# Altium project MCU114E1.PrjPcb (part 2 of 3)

## Sheet MCU114E1_Power.SchDoc
size 431 x 279 mm; Date: Not shown in title block; ApprovedBy: Not shown in title block; CheckedBy: Not shown in title block; Author: Not shown in title block; CompanyName: Not shown in title block; Engineer: Not shown in title block; Organization: Not shown in title block; Address1: Not shown in title block; Address2: Not shown in title block; Address3: Not shown in title block; Address4: Not shown in title block; DocumentNumber: 5; Revision: Use project parameter SCH_Rev; SheetNumber: 5; SheetTotal: 11; PageSetup: Record=PageOptions¦CenterHorizontal=True¦CenterVertical=True¦PrintScale=1.00¦XCorrection=1.00¦YCorrection=1.00¦PrintKind=0¦BorderSize=5000000¦LeftOffset=0¦BottomOffset=0¦Orientation=2¦PaperLength=1000¦PaperWidth=1000¦Scale=100¦PaperSource=15¦PrintQuality=600¦MediaType=1¦DitherType=10¦PaperKind=Letter¦PrintScaleMode=1

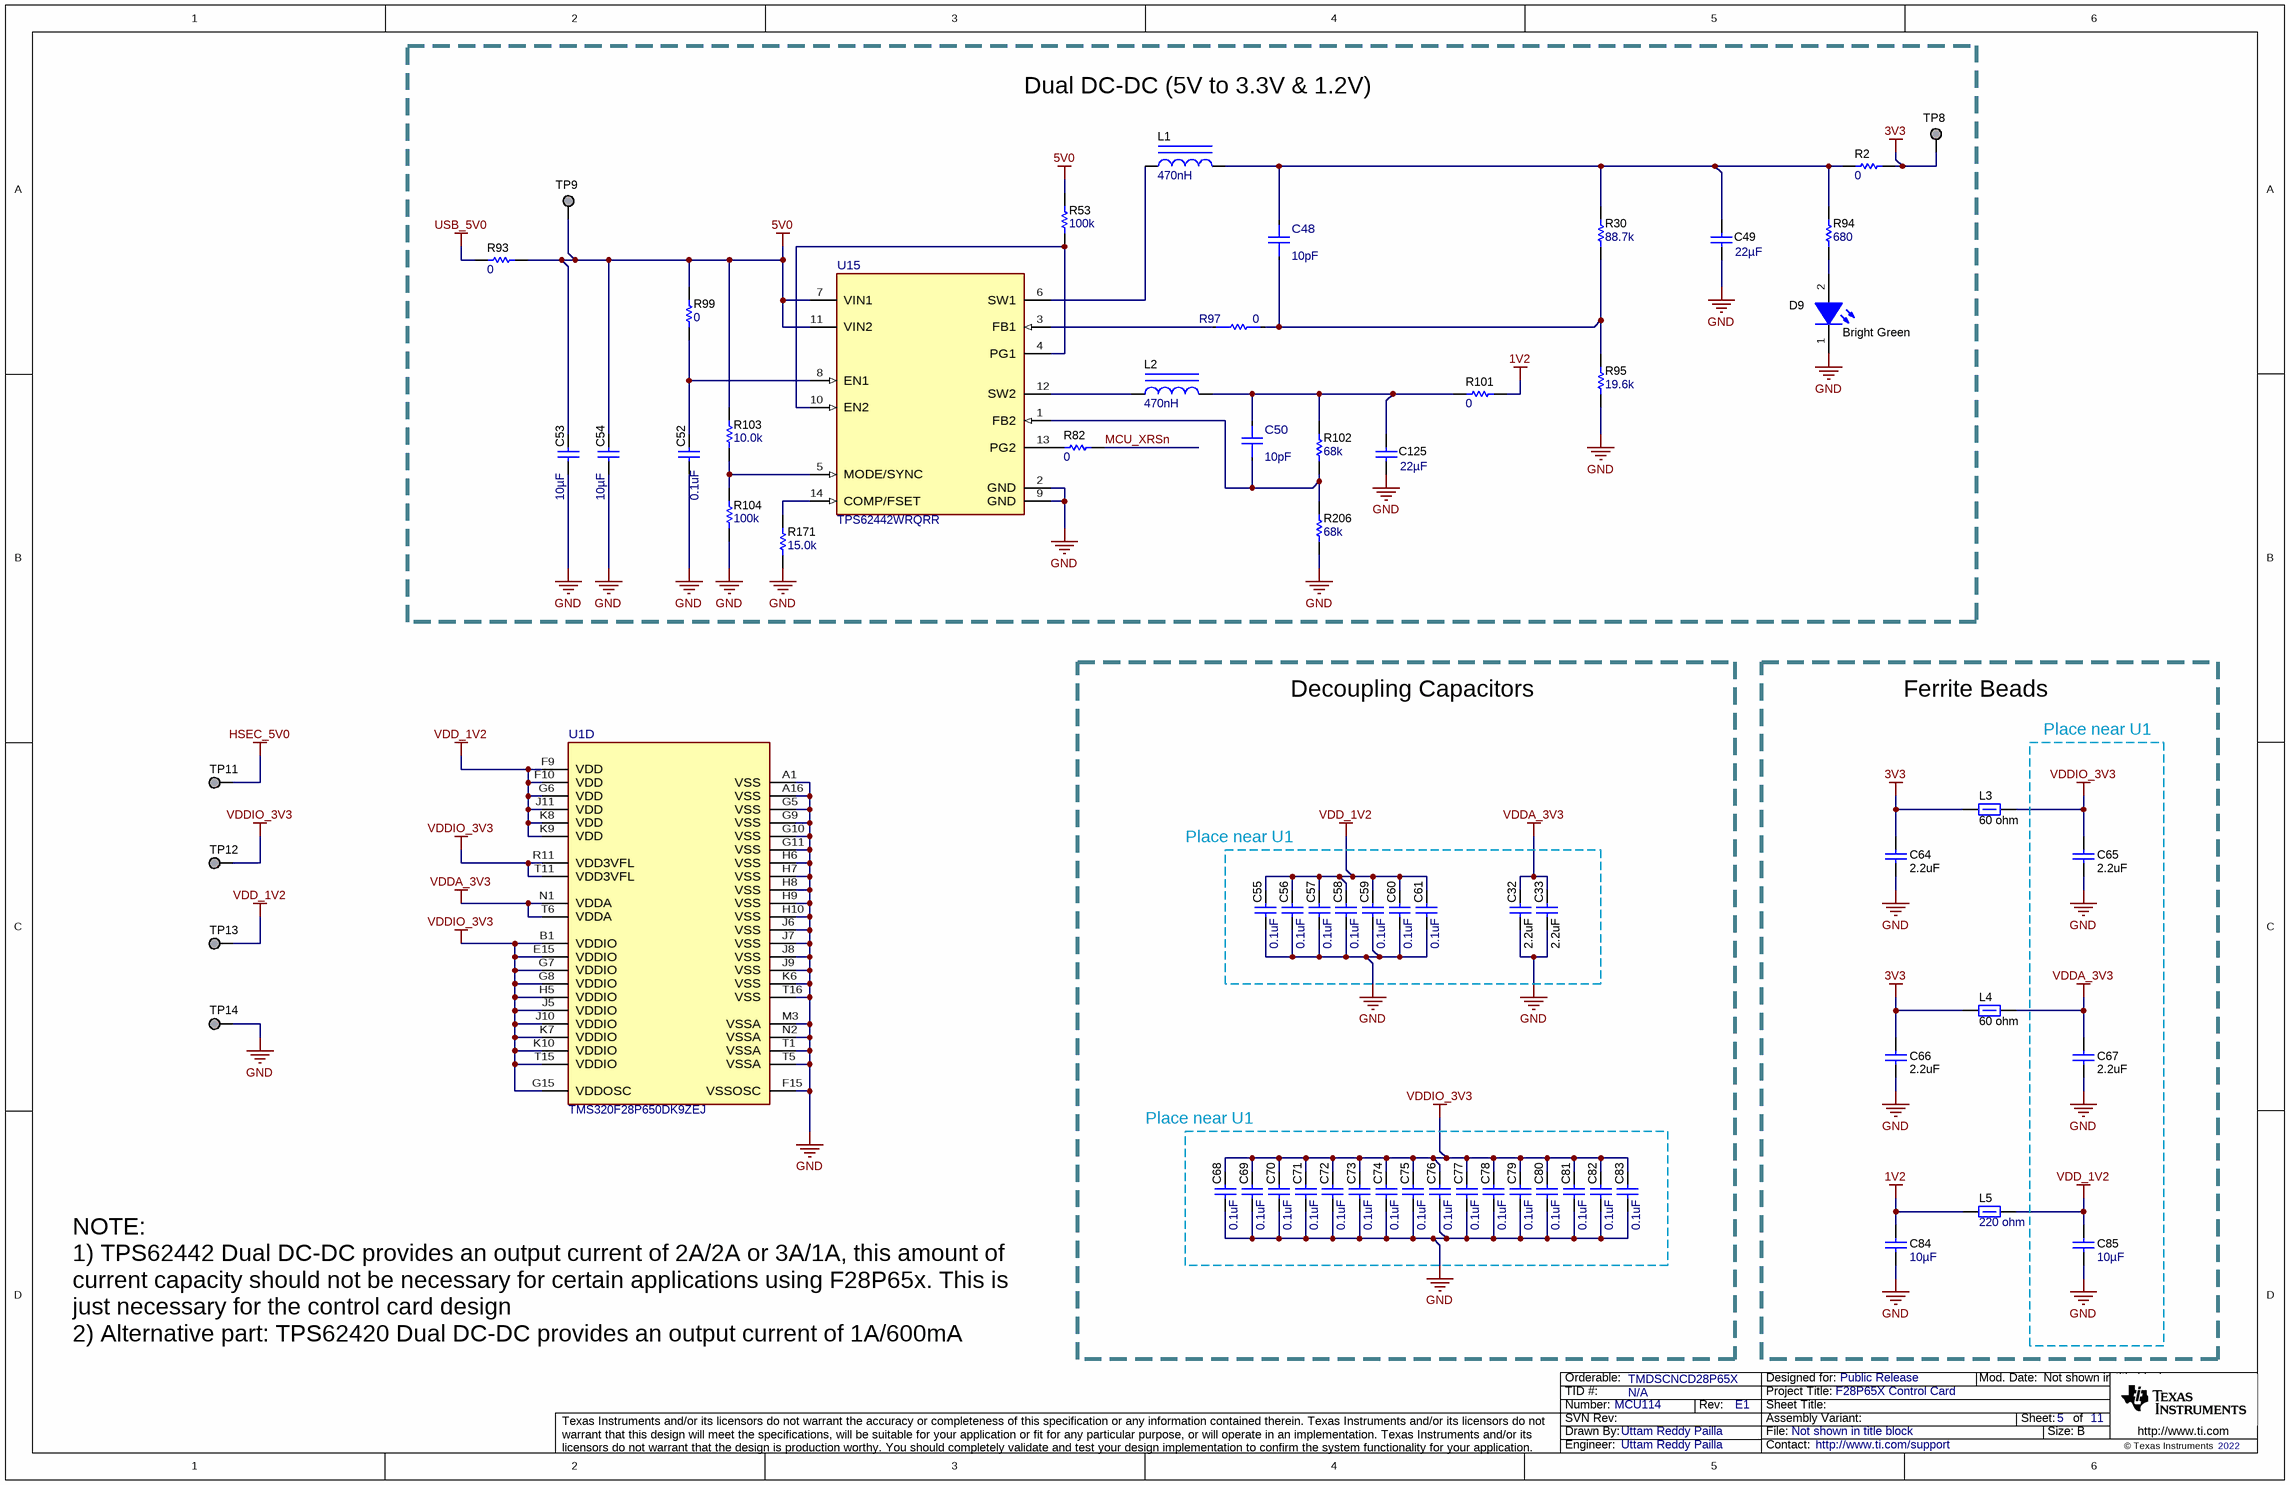
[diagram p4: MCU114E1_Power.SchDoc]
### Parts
C32  ValueDisplayed: 2.2uF  [0603]  (hidden comment: 885012106018)
C33  ValueDisplayed: 2.2uF  [0603]  (hidden comment: 885012106018)
C48  ValueDisplayed: 10pF  [FP-06033A100JAT2A_0603-MFG]  (hidden comment: 06033A100JAT2A)
C49  ValueDisplayed: 22µF  [0805_150]  (hidden comment: 885012107011)
C50  ValueDisplayed: 10pF  [FP-06033A100JAT2A_0603-MFG]  (hidden comment: 06033A100JAT2A)
C52  ValueDisplayed: 0.1uF  [0402]  (hidden comment: 885012205037)
C53  ValueDisplayed: 10µF  [0603]  (hidden comment: GRM188R61C106KAALD)
C54  ValueDisplayed: 10µF  [0603]  (hidden comment: GRM188R61C106KAALD)
C55  ValueDisplayed: 0.1uF  [0402]  (hidden comment: 885012205037)
C56  ValueDisplayed: 0.1uF  [0402]  (hidden comment: 885012205037)
C57  ValueDisplayed: 0.1uF  [0402]  (hidden comment: 885012205037)
C58  ValueDisplayed: 0.1uF  [0402]  (hidden comment: 885012205037)
C59  ValueDisplayed: 0.1uF  [0402]  (hidden comment: 885012205037)
C60  ValueDisplayed: 0.1uF  [0402]  (hidden comment: 885012205037)
C61  ValueDisplayed: 0.1uF  [0402]  (hidden comment: 885012205037)
C64  ValueDisplayed: 2.2uF  [0603]  (hidden comment: 885012106018)
C65  ValueDisplayed: 2.2uF  [0603]  (hidden comment: 885012106018)
C66  ValueDisplayed: 2.2uF  [0603]  (hidden comment: 885012106018)
C67  ValueDisplayed: 2.2uF  [0603]  (hidden comment: 885012106018)
C68  ValueDisplayed: 0.1uF  [0402]  (hidden comment: 885012205037)
C69  ValueDisplayed: 0.1uF  [0402]  (hidden comment: 885012205037)
C70  ValueDisplayed: 0.1uF  [0402]  (hidden comment: 885012205037)
C71  ValueDisplayed: 0.1uF  [0402]  (hidden comment: 885012205037)
C72  ValueDisplayed: 0.1uF  [0402]  (hidden comment: 885012205037)
C73  ValueDisplayed: 0.1uF  [0402]  (hidden comment: 885012205037)
C74  ValueDisplayed: 0.1uF  [0402]  (hidden comment: 885012205037)
C75  ValueDisplayed: 0.1uF  [0402]  (hidden comment: 885012205037)
C76  ValueDisplayed: 0.1uF  [0402]  (hidden comment: 885012205037)
C77  ValueDisplayed: 0.1uF  [0402]  (hidden comment: 885012205037)
C78  ValueDisplayed: 0.1uF  [0402]  (hidden comment: 885012205037)
C79  ValueDisplayed: 0.1uF  [0402]  (hidden comment: 885012205037)
C80  ValueDisplayed: 0.1uF  [0402]  (hidden comment: 885012205037)
C81  ValueDisplayed: 0.1uF  [0402]  (hidden comment: 885012205037)
C82  ValueDisplayed: 0.1uF  [0402]  (hidden comment: 885012205037)
C83  ValueDisplayed: 0.1uF  [0402]  (hidden comment: 885012205037)
C84  ValueDisplayed: 10µF  [0603]  (hidden comment: GRM188R61C106KAALD)
C85  ValueDisplayed: 10µF  [0603]  (hidden comment: GRM188R61C106KAALD)
C125  ValueDisplayed: 22µF  [0805_150]  (hidden comment: 885012107011)
D9  value Bright Green  [WL-SMCW_Green_0805]  (hidden comment: 150080VS75000)
L1  ValueDisplayed: 470nH  [XFL4015]  (hidden comment: XFL4015-471MEC)
L2  ValueDisplayed: 470nH  [XFL4015]  (hidden comment: XFL4015-471MEC)
L3  60 ohm  [0805_HV]
L4  60 ohm  [0805_HV]
L5  value 220 ohm  [0805_HV]  (hidden comment: BLM21PG221SN1D)
R2  ValueDisplayed: 0  [0402]  (hidden comment: CRCW04020000Z0EDHP)
R30  ValueDisplayed: 88.7k  [0402]  (hidden comment: CRCW040288K7FKED)
R53  ValueDisplayed: 100k  [0603]  (hidden comment: CRCW0603100KJNEA)
R82  ValueDisplayed: 0  [0402]  (hidden comment: CRCW04020000Z0EDHP)
R93  ValueDisplayed: 0  [0402]  (hidden comment: CRCW04020000Z0EDHP)
R94  ValueDisplayed: 680  [0402]  (hidden comment: CRCW0402680RJNED)
R95  ValueDisplayed: 19.6k  [0402]  (hidden comment: CRCW040219K6FKED)
R97  0  [FP-CRCW04020000Z0EDC_0402-MFG]
R99  ValueDisplayed: 0  [0402]  (hidden comment: CRCW04020000Z0EDHP)
R101  ValueDisplayed: 0  [0402]  (hidden comment: CRCW04020000Z0EDHP)
R102  ValueDisplayed: 68k  [0402]  (hidden comment: CRCW040268K0JNED)
R103  ValueDisplayed: 10.0k  [0402]  (hidden comment: AC0402FR-0710KL)
R104  ValueDisplayed: 100k  [0603]  (hidden comment: CRCW0603100KJNEA)
R171  ValueDisplayed: 15.0k  [0402]  (hidden comment: CRCW040215K0FKED)
R206  ValueDisplayed: 68k  [0402]  (hidden comment: CRCW040268K0JNED)
TP8  TESTPOINT  [TP_50MIL-25MILHOLE]  (value not drawn)  (no BOM)
TP9  TESTPOINT  [TP_50MIL-25MILHOLE]  (value not drawn)  (no BOM)
TP11  TESTPOINT  [TP_50MIL-25MILHOLE]  (value not drawn)  (no BOM)
TP12  TESTPOINT  [TP_50MIL-25MILHOLE]  (value not drawn)  (no BOM)
TP13  TESTPOINT  [TP_50MIL-25MILHOLE]  (value not drawn)  (no BOM)
TP14  TESTPOINT  [TP_50MIL-25MILHOLE]  (value not drawn)  (no BOM)
U1  TMS320F28P650DK9ZEJ  [ZEJ0256A-MFG]  (part D of 4)
U15  TPS62442WRQRR  [RQR0014A-MFG]

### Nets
1V2: C84.1 L5.1 R101.2
3V3: C64.1 C66.1 L3.1 L4.1 R2.2 TP8.1
5V0: C53.1 C54.1 R53.2 R93.1 R99.2 R103.2 TP9.1 U15.7(VIN1) U15.11(VIN2)
GND: C32.2 C33.2 C49.2 C52.2 C53.2 C54.2 C55.2 C56.2 C57.2 C58.2 C59.2 C60.2 C61.2 C64.2 C65.2 C66.2 C67.2 C68.2 C69.2 C70.2 C71.2 C72.2 C73.2 C74.2 C75.2 C76.2 C77.2 C78.2 C79.2 C80.2 C81.2 C82.2 C83.2 C84.2 C85.2 C125.2 D9.1(K) R95.1 R104.1 R171.1 R206.1 TP14.1 U1.A1(VSS) U1.A16(VSS) U1.F15(VSSOSC) U1.G5(VSS) U1.G9(VSS) U1.G10(VSS) U1.G11(VSS) U1.H6(VSS) U1.H7(VSS) U1.H8(VSS) U1.H9(VSS) U1.H10(VSS) U1.J6(VSS) U1.J7(VSS) U1.J8(VSS) U1.J9(VSS) U1.K6(VSS) U1.M3(VSSA) U1.N2(VSSA) U1.T1(VSSA) U1.T5(VSSA) U1.T16(VSS) U15.2(GND) U15.9(GND)
HSEC_5V0: TP11.1
USB_5V0: R93.2
VDD_1V2: C55.1 C56.1 C57.1 C58.1 C59.1 C60.1 C61.1 C85.1 L5.2 TP13.1 U1.F9(VDD) U1.F10(VDD) U1.G6(VDD) U1.J11(VDD) U1.K8(VDD) U1.K9(VDD)
VDDA_3V3: C32.1 C33.1 C67.1 L4.2 U1.N1(VDDA) U1.T6(VDDA)
VDDIO_3V3: C65.1 C68.1 C69.1 C70.1 C71.1 C72.1 C73.1 C74.1 C75.1 C76.1 C77.1 C78.1 C79.1 C80.1 C81.1 C82.1 C83.1 L3.2 TP12.1 U1.B1(VDDIO) U1.E15(VDDIO) U1.G7(VDDIO) U1.G8(VDDIO) U1.G15(VDDOSC) U1.H5(VDDIO) U1.J5(VDDIO) U1.J10(VDDIO) U1.K7(VDDIO) U1.K10(VDDIO) U1.R11(VDD3VFL) U1.T11(VDD3VFL) U1.T15(VDDIO)
MCU_XRSn: R82.1
NetC48_1: C48.1 R30.1 R95.2 R97.2
NetC48_2: C48.2 C49.1 L1.2 R2.1 R30.2 R94.2
NetC50_1: C50.1 R102.1 R206.2 U15.1(FB2)
NetC50_2: C50.2 C125.1 L2.2 R101.1 R102.2
NetC52_1: C52.1 R99.1 U15.8(EN1)
NetD9_2: D9.2(A) R94.1
NetL1_1: L1.1 U15.6(SW1)
NetL2_1: L2.1 U15.12(SW2)
NetR53_1: R53.1 U15.4(PG1) U15.10(EN2)
NetR82_2: R82.2 U15.13(PG2)
NetR97_1: R97.1 U15.3(FB1)
NetR103_1: R103.1 R104.2 U15.5(MODE/SYNC)
NetR171_2: R171.2 U15.14(COMP/FSET)

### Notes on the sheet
- Dual DC-DC (5V to 3.3V & 1.2V)
- Decoupling Capacitors
- Ferrite Beads
- Place near U1
- NOTE:
  1) TPS62442 Dual DC-DC provides an output current of 2A/2A or 3A/1A, this amount of current capacity should not be necessary for certain applications using F28P65x. This is just necessary for the control card design
  2) Alternative part: TPS62420 Dual DC-DC provides an output current of 1A/600mA

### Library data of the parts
C32 C33 C64-C67 = CMP-0006825-5: CAP, CERM, 2.2 uF, 16 V, +/- 20%, X5R, 0603; Manufacturer: Wurth Elektronik; TaMin_C: -55°C; Polarized: N; SizeAreaWB_mm2: 4.68; Value1: Unknown; U/M: EA; Value: 2.2uF; TaMax_C: 85°C; SizeZ_mm: 1; SizeX_mm: 1.6; SizeY_mm: 0.8; Value2: 16V; SizeArea_mm2: 1.28; Cap_F: 2.2µF; AEC Category: Q200
C48 C50 = CMP-0090724-1: 10pF ±5% 25V Ceramic Capacitor C0G, NP0 0603 (1608 Metric); Manufacturer: AVX; TempCo: 30ppm/°C; AEC Qualified: No; SizeZ_mm: 0.9mm
C49 C125 = CMP-0078153-1: CAP, CERM, 22 µF, 10 V,+/- 20%, X5R, 0805; Manufacturer: Wurth Elektronik; TaMin_C: -55°C; Polarized: N; SizeAreaWB_mm2: 6.75; U/M: EA; Value: 22uF; TaMax_C: 85°C; SizeZ_mm: 1.5; SizeX_mm: 2; SizeY_mm: 1.25; Cap_Case: 0805; Value2: 10V; SizeArea_mm2: 2.5; AEC Category: Q200
C52 C55-C61 C68-C83 = CMP-0006228-2: CAP, CERM, 0.1 uF, 16 V, +/- 10%, X7R, 0402; Manufacturer: Wurth Elektronik; TaMin_C: -55°C; Polarized: N; SizeAreaWB_mm2: 3; Value1: Unknown; U/M: EA; Value: 0.1uF; TaMax_C: 125°C; SizeZ_mm: 0.6; SizeX_mm: 1; SizeY_mm: 0.5; Value2: 16V; Cap_F: 100nF; AEC Category: Q200
C53 C54 C84 C85 = CMP-0086225-1: CAP, CERM, 10 µF, 16 V,+/- 10%, X5R, 0603; Manufacturer: MuRata; SizeZ_mm: 1; SizeX_mm: 1.6; SizeArea_mm2: 1.28; VDC_V: 16V; U/M: EA; AEC Category: Q200; SizeY_mm: 0.8; Polarized: N; TaMax_C: 85°C; Value: 10uF; SizeAreaWB_mm2: 4.68; TaMin_C: -55°C
D9 = CMP-0002960-2: LED, Bright Green, SMD; Manufacturer: Wurth Elektronik; Type: AlInGaP; Vf_V: 2V; Io_A: 20mA; Vr_V: 5V; Tjmax_C: 85°C; Power_TotalModule: 72mW; Value1: 0.072W; Angle: 140; U/M: EA
L1 L2 = CMP-0061147-1: Inductor, Shielded, Composite, 470 nH, 3.5 A, 0.0076 ohm, SMD; Manufacturer: Coilcraft; Isat: 3.5A @ 10% inductance drop; Irms: 9.1A @ 20C rise; Green_Lifecycle: Not Set; SizeAreaWB_mm2: 28.09; DCR_ohm: 7.6m; Green_REACh: Incomplete; Value: 470nH; Imax_A: 3.5A; SizeZ_mm: 1.6; SizeX_mm: 4.3; SizeArea_mm2: 18.49; AEC Category: Q200
L3 L4 = CMP-0003093-1: Ferrite Bead, 60 ohm @ 100 MHz, 3 A, 0805; Manufacturer: Wurth Elektronik; PartNumber: 742792063; Ztyp@1GHz_Ohm: 95.384; ZTyp@100MHz_Ohm: 60; SizeAreaWB_mm2: 6.75; DCR_ohm: 0.025; Value1: 0.025 ohm; Imax_A: 3A; SizeZ_mm: 1.45; SizeX_mm: 2; SizeY_mm: 1.25; SizeArea_mm2: 2.5
L5 = CMP-0003363-1: Ferrite Bead, 220 ohm @ 100 MHz, 2 A, 0805; Manufacturer: MuRata; Imax_A: 2A; DCR_ohm: 45m; Value1: 0.045 ohm; ZTyp@100MHz_Ohm: 220; SizeArea_mm2: 2.5; SizeAreaWB_mm2: 6.75; SizeX_mm: 2; SizeY_mm: 1.25; SizeZ_mm: 1.45
R2 R82 R93 R99 R101 = CMP-0081856-1: RES, 0, 0%, 0.2 W, AEC-Q200 Grade 0, 0402; Manufacturer: Vishay-Dale; SizeAreaWB_mm2: 3; SizeArea_mm2: 0.5; AEC Qualified: Y; AEC Category: Q200; Value: 0; SizeZ_mm: 0.6; Power_W: 200mW; VDC_V: 50V; Value2: 0.2W; SizeX_mm: 1
R30 = CMP-0026586-2: RES, 88.7 k, 1%, 0.063 W, AEC-Q200 Grade 0, 0402; Manufacturer: Vishay-Dale; Power_W: 63mW; TempCo: 100 ppm/C; Value_Code: 88k7; Value: 88.7k; EIA_Code: E96; SizeX_mm: 1; SizeY_mm: 0.5; SizeZ_mm: 0.6; Value2: 0.063W; AEC Qualified: Y; VDC_V: 50V; AEC Category: Q200; AEC Grade: 0
R53 R104 = CMP-0025698-4: RES, 100 k, 5%, 0.1 W, AEC-Q200 Grade 0, 0603; Manufacturer: Vishay-Dale; Power_W: 100mW; TempCo: 200 ppm/C; Value: 100k; EIA_Code: E24; SizeX_mm: 1.6; SizeY_mm: 0.8; SizeZ_mm: 1; Value2: 0.1W; SizeArea_mm2: 1.28; AEC Qualified: Y; VDC_V: 75V; AEC Category: Q200; AEC Grade: 0
R94 = CMP-0026962-3: RES, 680, 5%, 0.063 W, AEC-Q200 Grade 0, 0402; Manufacturer: Vishay-Dale; Power_W: 63mW; TempCo: 200 ppm/C; Value_Code: 680R; Value: 680; EIA_Code: E24; SizeX_mm: 1; SizeY_mm: 0.5; SizeZ_mm: 0.6; Value2: 0.063W; AEC Qualified: Y; VDC_V: 50V; AEC Category: Q200; AEC Grade: 0
R95 = CMP-0026068-3: RES, 19.6 k, 1%, 0.063 W, AEC-Q200 Grade 0, 0402; Manufacturer: Vishay-Dale; Power_W: 63mW; TempCo: 100 ppm/C; Value_Code: 19k6; Value: 19.6k; EIA_Code: E96; SizeX_mm: 1; SizeY_mm: 0.5; SizeZ_mm: 0.6; Value2: 0.063W; AEC Qualified: Y; VDC_V: 50V; AEC Category: Q200; AEC Grade: 0
R97 = CMP-0093210-1: Jumper 0.063W, 1/16W Chip Resistor 0402 (1005 Metric) - Thick Film; Manufacturer: Vishay; Part Number: CRCW04020000Z0EDC; AEC Qualified: No; VDC_V: 50V; Power_W: 63mW; SizeZ_mm: 0.35mm
R102 R206 = CMP-0026963-3: RES, 68 k, 5%, 0.063 W, AEC-Q200 Grade 0, 0402; Manufacturer: Vishay-Dale; Power_W: 63mW; TempCo: 200 ppm/C; Value_Code: 68k0; Value: 68k; EIA_Code: E24; SizeX_mm: 1; SizeY_mm: 0.5; SizeZ_mm: 0.6; Value2: 0.063W; AEC Qualified: Y; VDC_V: 50V; AEC Category: Q200; AEC Grade: 0
R103 = CMP-0077731-1: RES, 10.0 k, 1%, 0.063 W, AEC-Q200 Grade 0, 0402; Manufacturer: Yageo America; Power_W: 63mW; TempCo: 100 ppm/C; Value_Code: 10k0; U/M: EA; Value: 10.0k; EIA_Code: E96; Res_ohm: 10k; SizeX_mm: 1.0; SizeY_mm: 0.5; SizeZ_mm: 0.6; Value2: 0.063W; AEC Qualified: Y; VDC_V: 50V; AEC Grade: 0; AEC Category: Q200
R171 = CMP-0026027-3: RES, 15.0 k, 1%, 0.063 W, AEC-Q200 Grade 0, 0402; Manufacturer: Vishay-Dale; Power_W: 63mW; TempCo: 100 ppm/C; Value_Code: 15k0; Value: 15.0k; EIA_Code: E96; Res_ohm: 15k; SizeX_mm: 1; SizeY_mm: 0.5; SizeZ_mm: 0.6; Value2: 0.063W; AEC Qualified: Y; VDC_V: 50V; AEC Category: Q200; AEC Grade: 0
TP8 TP9 TP11-TP14 = CMP-0078143-3: TEST POINT.  No entry in BOM.
U1 = CMP-0096042-2: Real-Time Microcontroller NFBGA256; Manufacturer: Texas Instruments; AEC Category: Q200; Core Architecture: C28x; Data Bus Width: 32bits; Number Of Ethernet Channels: 1; Number Of Cores: 2; CompType: IC; Number Of I/Os: 159; Interface: I2C,SPI,UART,CAN,USB,LIN,SCI,Ethernet,Other; Number Of Pwm Channels: 36; AEC Qualified: No; Number Of Timers/Counters: 6; Standoff Height: 0.35mm; Number Of Spi Channels: 4; SizeZ_mm: 1.4mm; Number Of Adc Channels: 40; Ram Size: 248KBytes; Frequency_Fixed: 200MHz; Memory Size: 1.28MBytes; Number Of A/D Converters: 3; Memory Type: FLASH
U15 = CMP-0094192-1: 2.7-V to 6-V Adjustable-Frequency Dual Step-Down Converter in QFN package; Manufacturer: Texas Instruments; Number Of Outputs: 2; Max Duty Cycle: 100%; TaMin_C: -40°C; Standoff Height: 0mm; AEC Grade: NA; AEC Qualified: No; Output Type: AdjustableProgrammable; Max Supply Voltage: 6V; Min Supply Voltage: 2.7V; TaMax_C: +125°C; SizeZ_mm: 1mm; Switching Topology: Buck; TJmax_C: +150°C; Output Voltage: 0.6-5.5V; Nominal Supply Current: 22-33uA; Switching Frequency: 1.8-4MHz

## Sheet MCU114E1_EtherCAT.SchDoc
size 431 x 279 mm; Date: Not shown in title block; ApprovedBy: Not shown in title block; CheckedBy: Not shown in title block; Author: Not shown in title block; CompanyName: Not shown in title block; Engineer: Not shown in title block; Organization: Not shown in title block; Address1: Not shown in title block; Address2: Not shown in title block; Address3: Not shown in title block; Address4: Not shown in title block; DocumentNumber: 6; Revision: Use project parameter SCH_Rev; SheetNumber: 6; SheetTotal: 11; PageSetup: Record=PageOptions¦CenterHorizontal=True¦CenterVertical=True¦PrintScale=1.00¦XCorrection=1.00¦YCorrection=1.00¦PrintKind=0¦BorderSize=5000000¦LeftOffset=0¦BottomOffset=0¦Orientation=2¦PaperLength=1000¦PaperWidth=1000¦Scale=100¦PaperSource=15¦PrintQuality=600¦MediaType=1¦DitherType=10¦PaperKind=Letter¦PrintScaleMode=1

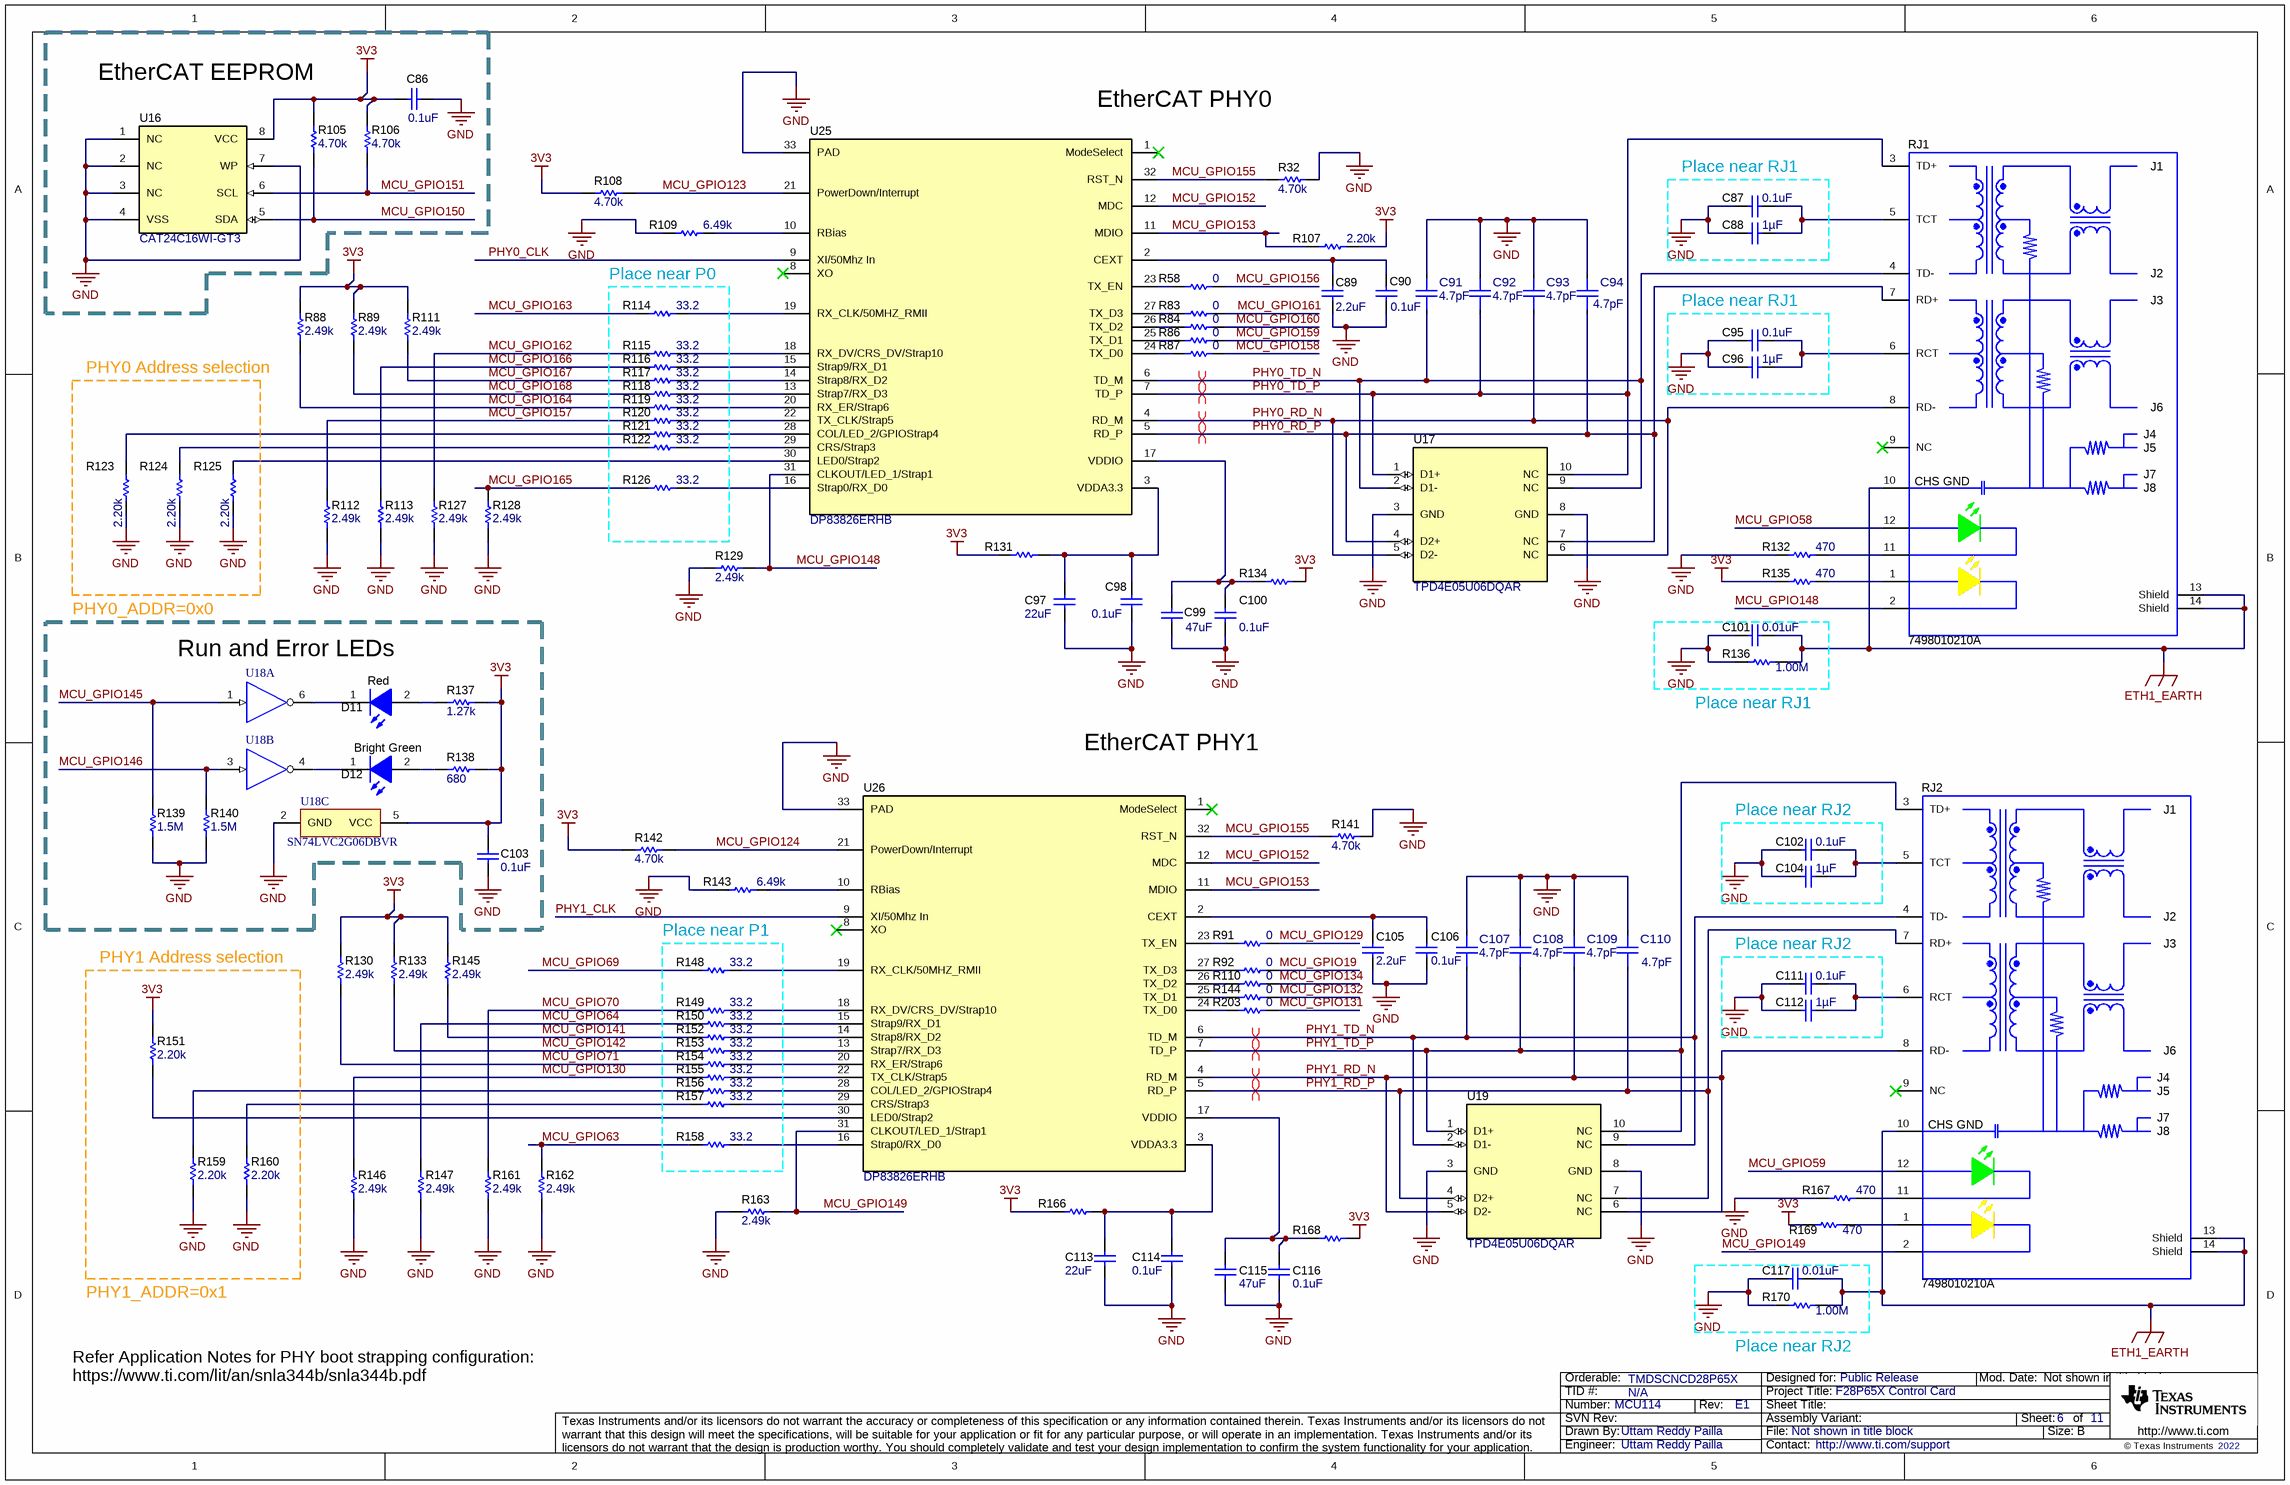
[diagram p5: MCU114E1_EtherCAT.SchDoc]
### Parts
C86  ValueDisplayed: 0.1uF  [0402]  (hidden comment: 885012205037)
C87  ValueDisplayed: 0.1uF  [0402]  (hidden comment: CGA2B3X7R1H104K050BB)
C88  ValueDisplayed: 1µF  [0402]  (hidden comment: GRM155R61E105KE11D)
C89  ValueDisplayed: 2.2uF  [0402_065]  (hidden comment: C1005X5R1V225K050BC)
C90  ValueDisplayed: 0.1uF  [0402]  (hidden comment: 885012205037)
C91  ValueDisplayed: 4.7pF  [FP-885012005053_0402-MFG]  (hidden comment: 885012005053)
C92  ValueDisplayed: 4.7pF  [FP-885012005053_0402-MFG]  (hidden comment: 885012005053)
C93  ValueDisplayed: 4.7pF  [FP-885012005053_0402-MFG]  (hidden comment: 885012005053)
C94  ValueDisplayed: 4.7pF  [FP-885012005053_0402-MFG]  (hidden comment: 885012005053)
C95  ValueDisplayed: 0.1uF  [0402]  (hidden comment: CGA2B3X7R1H104K050BB)
C96  ValueDisplayed: 1µF  [0402]  (hidden comment: GRM155R61E105KE11D)
C97  ValueDisplayed: 22uF  [0603]  (hidden comment: GRM188R61A226ME15D)
C98  ValueDisplayed: 0.1uF  [0402]  (hidden comment: 885012205037)
C99  ValueDisplayed: 47uF  [0603]  (hidden comment: GRM188R60J476ME15D)
C100  ValueDisplayed: 0.1uF  [0402]  (hidden comment: 885012205037)
C101  ValueDisplayed: 0.01uF  [0402]  (hidden comment: GRM155R71H103KA88D)
C102  ValueDisplayed: 0.1uF  [0402]  (hidden comment: CGA2B3X7R1H104K050BB)
C103  ValueDisplayed: 0.1uF  [0402]  (hidden comment: 885012205037)
C104  ValueDisplayed: 1µF  [0402]  (hidden comment: GRM155R61E105KE11D)
C105  ValueDisplayed: 2.2uF  [0402_065]  (hidden comment: C1005X5R1V225K050BC)
C106  ValueDisplayed: 0.1uF  [0402]  (hidden comment: 885012205037)
C107  ValueDisplayed: 4.7pF  [FP-885012005053_0402-MFG]  (hidden comment: 885012005053)
C108  ValueDisplayed: 4.7pF  [FP-885012005053_0402-MFG]  (hidden comment: 885012005053)
C109  ValueDisplayed: 4.7pF  [FP-885012005053_0402-MFG]  (hidden comment: 885012005053)
C110  ValueDisplayed: 4.7pF  [FP-885012005053_0402-MFG]  (hidden comment: 885012005053)
C111  ValueDisplayed: 0.1uF  [0402]  (hidden comment: CGA2B3X7R1H104K050BB)
C112  ValueDisplayed: 1µF  [0402]  (hidden comment: GRM155R61E105KE11D)
C113  ValueDisplayed: 22uF  [0603]  (hidden comment: GRM188R61A226ME15D)
C114  ValueDisplayed: 0.1uF  [0402]  (hidden comment: 885012205037)
C115  ValueDisplayed: 47uF  [0603]  (hidden comment: GRM188R60J476ME15D)
C116  ValueDisplayed: 0.1uF  [0402]  (hidden comment: 885012205037)
C117  ValueDisplayed: 0.01uF  [0402]  (hidden comment: GRM155R71H103KA88D)
D11  value Red  [WL-SMCW_RED_0805]  (hidden comment: 150080SS75000)
D12  value Bright Green  [WL-SMCW_Green_0805]  (hidden comment: 150080VS75000)
R32  ValueDisplayed: 4.70k  [0402]  (hidden comment: CRG0402F4K7)
R58  ValueDisplayed: 0  [0402]  (hidden comment: CRCW04020000Z0EDHP)
R83  ValueDisplayed: 0  [0402]  (hidden comment: CRCW04020000Z0EDHP)
R84  ValueDisplayed: 0  [0402]  (hidden comment: CRCW04020000Z0EDHP)
R86  ValueDisplayed: 0  [0402]  (hidden comment: CRCW04020000Z0EDHP)
R87  ValueDisplayed: 0  [0402]  (hidden comment: CRCW04020000Z0EDHP)
R88  ValueDisplayed: 2.49k  [0402]  (hidden comment: CRCW04022K49FKED)
R89  ValueDisplayed: 2.49k  [0402]  (hidden comment: CRCW04022K49FKED)
R91  ValueDisplayed: 0  [0402]  (hidden comment: CRCW04020000Z0EDHP)
R92  ValueDisplayed: 0  [0402]  (hidden comment: CRCW04020000Z0EDHP)
R105  ValueDisplayed: 4.70k  [0402]  (hidden comment: CRG0402F4K7)
R106  ValueDisplayed: 4.70k  [0402]  (hidden comment: CRG0402F4K7)
R107  ValueDisplayed: 2.20k  [0402]  (hidden comment: CRCW04022K20FKED)
R108  ValueDisplayed: 4.70k  [0402]  (hidden comment: CRG0402F4K7)
R109  ValueDisplayed: 6.49k  [0402]  (hidden comment: CRCW04026K49FKED)
R110  ValueDisplayed: 0  [0402]  (hidden comment: CRCW04020000Z0EDHP)
R111  ValueDisplayed: 2.49k  [0402]  (hidden comment: CRCW04022K49FKED)
R112  ValueDisplayed: 2.49k  [0402]  (hidden comment: CRCW04022K49FKED)
R113  ValueDisplayed: 2.49k  [0402]  (hidden comment: CRCW04022K49FKED)
R114  ValueDisplayed: 33.2  [0402]  (hidden comment: CRCW040233R2FKED)
R115  ValueDisplayed: 33.2  [0402]  (hidden comment: CRCW040233R2FKED)
R116  ValueDisplayed: 33.2  [0402]  (hidden comment: CRCW040233R2FKED)
R117  ValueDisplayed: 33.2  [0402]  (hidden comment: CRCW040233R2FKED)
R118  ValueDisplayed: 33.2  [0402]  (hidden comment: CRCW040233R2FKED)
R119  ValueDisplayed: 33.2  [0402]  (hidden comment: CRCW040233R2FKED)
R120  ValueDisplayed: 33.2  [0402]  (hidden comment: CRCW040233R2FKED)
R121  ValueDisplayed: 33.2  [0402]  (hidden comment: CRCW040233R2FKED)
R122  ValueDisplayed: 33.2  [0402]  (hidden comment: CRCW040233R2FKED)
R123  ValueDisplayed: 2.20k  [0402]  (hidden comment: CRCW04022K20FKED)
R124  ValueDisplayed: 2.20k  [0402]  (hidden comment: CRCW04022K20FKED)
R125  ValueDisplayed: 2.20k  [0402]  (hidden comment: CRCW04022K20FKED)
R126  ValueDisplayed: 33.2  [0402]  (hidden comment: CRCW040233R2FKED)
R127  ValueDisplayed: 2.49k  [0402]  (hidden comment: CRCW04022K49FKED)
R128  ValueDisplayed: 2.49k  [0402]  (hidden comment: CRCW04022K49FKED)
R129  ValueDisplayed: 2.49k  [0402]  (hidden comment: CRCW04022K49FKED)
R130  ValueDisplayed: 2.49k  [0402]  (hidden comment: CRCW04022K49FKED)
R131  RMCF0402ZT0R00  [FP-RMCF0402ZT0R00_0402 (1005 metric)-0]  (value not drawn)
R132  ValueDisplayed: 470  [0603]  (hidden comment: CRCW0603470RJNEA)
R133  ValueDisplayed: 2.49k  [0402]  (hidden comment: CRCW04022K49FKED)
R134  RMCF0402ZT0R00  [FP-RMCF0402ZT0R00_0402 (1005 metric)-0]  (value not drawn)
R135  ValueDisplayed: 470  [0603]  (hidden comment: CRCW0603470RJNEA)
R136  ValueDisplayed: 1.00M  [0402]  (hidden comment: RMCF0402FT1M00)
R137  ValueDisplayed: 1.27k  [0402]  (hidden comment: CRCW04021K27FKED)
R138  ValueDisplayed: 680  [0402]  (hidden comment: CRCW0402680RJNED)
R139  ValueDisplayed: 1.5M  [0402]  (hidden comment: CRCW04021M50JNED)
R140  ValueDisplayed: 1.5M  [0402]  (hidden comment: CRCW04021M50JNED)
R141  ValueDisplayed: 4.70k  [0402]  (hidden comment: CRG0402F4K7)
R142  ValueDisplayed: 4.70k  [0402]  (hidden comment: CRG0402F4K7)
R143  ValueDisplayed: 6.49k  [0402]  (hidden comment: CRCW04026K49FKED)
R144  ValueDisplayed: 0  [0402]  (hidden comment: CRCW04020000Z0EDHP)
R145  ValueDisplayed: 2.49k  [0402]  (hidden comment: CRCW04022K49FKED)
R146  ValueDisplayed: 2.49k  [0402]  (hidden comment: CRCW04022K49FKED)
R147  ValueDisplayed: 2.49k  [0402]  (hidden comment: CRCW04022K49FKED)
R148  ValueDisplayed: 33.2  [0402]  (hidden comment: CRCW040233R2FKED)
R149  ValueDisplayed: 33.2  [0402]  (hidden comment: CRCW040233R2FKED)
R150  ValueDisplayed: 33.2  [0402]  (hidden comment: CRCW040233R2FKED)
R151  ValueDisplayed: 2.20k  [0402]  (hidden comment: CRCW04022K20FKED)
R152  ValueDisplayed: 33.2  [0402]  (hidden comment: CRCW040233R2FKED)
R153  ValueDisplayed: 33.2  [0402]  (hidden comment: CRCW040233R2FKED)
R154  ValueDisplayed: 33.2  [0402]  (hidden comment: CRCW040233R2FKED)
R155  ValueDisplayed: 33.2  [0402]  (hidden comment: CRCW040233R2FKED)
R156  ValueDisplayed: 33.2  [0402]  (hidden comment: CRCW040233R2FKED)
R157  ValueDisplayed: 33.2  [0402]  (hidden comment: CRCW040233R2FKED)
R158  ValueDisplayed: 33.2  [0402]  (hidden comment: CRCW040233R2FKED)
R159  ValueDisplayed: 2.20k  [0402]  (hidden comment: CRCW04022K20FKED)
R160  ValueDisplayed: 2.20k  [0402]  (hidden comment: CRCW04022K20FKED)
R161  ValueDisplayed: 2.49k  [0402]  (hidden comment: CRCW04022K49FKED)
R162  ValueDisplayed: 2.49k  [0402]  (hidden comment: CRCW04022K49FKED)
R163  ValueDisplayed: 2.49k  [0402]  (hidden comment: CRCW04022K49FKED)
R166  RMCF0402ZT0R00  [FP-RMCF0402ZT0R00_0402 (1005 metric)-0]  (value not drawn)
R167  ValueDisplayed: 470  [0603]  (hidden comment: CRCW0603470RJNEA)
R168  RMCF0402ZT0R00  [FP-RMCF0402ZT0R00_0402 (1005 metric)-0]  (value not drawn)
R169  ValueDisplayed: 470  [0603]  (hidden comment: CRCW0603470RJNEA)
R170  ValueDisplayed: 1.00M  [0402]  (hidden comment: RMCF0402FT1M00)
R203  ValueDisplayed: 0  [0402]  (hidden comment: CRCW04020000Z0EDHP)
RJ1  7498010210A  [Wurth_7498010210A]
RJ2  7498010210A  [Wurth_7498010210A]
U16  CAT24C16WI-GT3  [SOIC-8]
U17  TPD4E05U06DQAR  [DQA0010A]
U18  SN74LVC2G06DBVR  [DBV0006A_N]  (parts A,B,C of 3)
U19  TPD4E05U06DQAR  [DQA0010A]
U25  DP83826ERHB  [RHB0032M]
U26  DP83826ERHB  [RHB0032M]

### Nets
3V3: C86.2 C103.1 R88.2 R89.2 R105.2 R106.2 R107.2 R108.1 R111.2 R130.2 R131.1 R133.2 R134.2 R135.1 R137.2 R138.1 R142.1 R145.2 R151.2 R166.1 R168.2 R169.1 U16.8(VCC) U18.5(VCC)
ETH1_EARTH: C101.2 C117.2 R136.2 R170.2 RJ1.10(CHS_GND) RJ1.13(Shield) RJ1.14(Shield) RJ2.10(CHS_GND) RJ2.13(Shield) RJ2.14(Shield)
GND: C86.1 C87.1 C88.1 C89.2 C90.2 C91.2 C92.2 C93.2 C94.2 C95.1 C96.1 C97.2 C98.2 C99.2 C100.2 C101.1 C102.1 C103.2 C104.1 C105.2 C106.2 C107.2 C108.2 C109.2 C110.2 C111.1 C112.1 C113.2 C114.1 C115.2 C116.1 C117.1 R32.2 R109.1 R112.1 R113.1 R123.1 R124.1 R125.1 R127.1 R128.1 R129.1 R132.1 R136.1 R139.2 R140.2 R141.2 R143.1 R146.1 R147.1 R159.1 R160.1 R161.1 R162.1 R163.2 R167.1 R170.1 U16.1(NC) U16.2(NC) U16.3(NC) U16.4(VSS) U16.7(WP) U17.3(GND) U17.8(GND) U18.2(GND) U19.3(GND) U19.8(GND) U25.33(PAD) U26.33(PAD)
MCU_GPIO19: R92.2
MCU_GPIO58: RJ1.12(LEFT_LED_ANODE)
MCU_GPIO59: RJ2.12(LEFT_LED_ANODE)
MCU_GPIO63: R158.1 R162.2
MCU_GPIO64: R147.2 R150.1
MCU_GPIO69: R148.1
MCU_GPIO70: R149.1 R161.2
MCU_GPIO71: R130.1 R154.1
MCU_GPIO123: R108.2 U25.21(PowerDown/Interrupt)
MCU_GPIO124: R142.2 U26.21(PowerDown/Interrupt)
MCU_GPIO129: R91.2
MCU_GPIO130: R146.2 R155.1
MCU_GPIO131: R203.2
MCU_GPIO132: R144.2
MCU_GPIO134: R110.2
MCU_GPIO141: R145.1 R152.1
MCU_GPIO142: R133.1 R153.1
MCU_GPIO145: R139.1 U18.1(1A)
MCU_GPIO146: R140.1 U18.3(2A)
MCU_GPIO148: R129.2 RJ1.2(RIGHT_LED_CATHODE) U25.31(CLKOUT/LED_1/Strap1)
MCU_GPIO149: R163.1 RJ2.2(RIGHT_LED_CATHODE) U26.31(CLKOUT/LED_1/Strap1)
MCU_GPIO150: R105.1 U16.5(SDA)
MCU_GPIO151: R106.1 U16.6(SCL)
MCU_GPIO152: U25.12(MDC) U26.12(MDC)
MCU_GPIO153: R107.1 U25.11(MDIO) U26.11(MDIO)
MCU_GPIO155: R32.1 R141.1 U25.32(RST_N) U26.32(RST_N)
MCU_GPIO156: R58.2
MCU_GPIO157: R112.2 R120.1
MCU_GPIO158: R87.2
MCU_GPIO159: R86.2
MCU_GPIO160: R84.2
MCU_GPIO161: R83.2
MCU_GPIO162: R115.1 R127.2
MCU_GPIO163: R114.1
MCU_GPIO164: R88.1 R119.1
MCU_GPIO165: R126.1 R128.2
MCU_GPIO166: R113.2 R116.1
MCU_GPIO167: R111.1 R117.1
MCU_GPIO168: R89.1 R118.1
PHY0_CLK: U25.9(XI/50Mhz_In)
PHY0_RD_N: C93.1 RJ1.8(RD-) U17.5(D2-) U17.6(NC) U25.4(RD_M)
PHY0_RD_P: C94.1 RJ1.7(RD+) U17.4(D2+) U17.7(NC) U25.5(RD_P)
PHY0_TD_N: C91.1 RJ1.4(TD-) U17.2(D1-) U17.9(NC) U25.6(TD_M)
PHY0_TD_P: C92.1 RJ1.3(TD+) U17.1(D1+) U17.10(NC) U25.7(TD_P)
PHY1_CLK: U26.9(XI/50Mhz_In)
PHY1_RD_N: C109.1 RJ2.8(RD-) U19.5(D2-) U19.6(NC) U26.4(RD_M)
PHY1_RD_P: C110.1 RJ2.7(RD+) U19.4(D2+) U19.7(NC) U26.5(RD_P)
PHY1_TD_N: C107.1 RJ2.4(TD-) U19.2(D1-) U19.9(NC) U26.6(TD_M)
PHY1_TD_P: C108.1 RJ2.3(TD+) U19.1(D1+) U19.10(NC) U26.7(TD_P)
NetC87_2: C87.2 C88.2 RJ1.5(TCT)
NetC89_1: C89.1 C90.1 U25.2(CEXT)
NetC95_2: C95.2 C96.2 RJ1.6(RCT)
NetC97_1: C97.1 C98.1 R131.2 U25.3(VDDA3.3)
NetC99_1: C99.1 C100.1 R134.1 U25.17(VDDIO)
NetC102_2: C102.2 C104.2 RJ2.5(TCT)
NetC105_1: C105.1 C106.1 U26.2(CEXT)
NetC111_2: C111.2 C112.2 RJ2.6(RCT)
NetC113_1: C113.1 C114.2 R166.2 U26.3(VDDA3.3)
NetC115_1: C115.1 C116.2 R168.1 U26.17(VDDIO)
NetD11_1: D11.1(K) U18.6(1Y)
NetD11_2: D11.2(A) R137.1
NetD12_1: D12.1(K) U18.4(2Y)
NetD12_2: D12.2(A) R138.2
NetR58_1: R58.1 U25.23(TX_EN)
NetR83_1: R83.1 U25.27(TX_D3)
NetR84_1: R84.1 U25.26(TX_D2)
NetR86_1: R86.1 U25.25(TX_D1)
NetR87_1: R87.1 U25.24(TX_D0)
NetR91_1: R91.1 U26.23(TX_EN)
NetR92_1: R92.1 U26.27(TX_D3)
NetR109_2: R109.2 U25.10(RBias)
NetR110_1: R110.1 U26.26(TX_D2)
NetR114_2: R114.2 U25.19(RX_CLK/50MHZ_RMII)
NetR115_2: R115.2 U25.18(RX_DV/CRS_DV/Strap10)
NetR116_2: R116.2 U25.15(Strap9/RX_D1)
NetR117_2: R117.2 U25.14(Strap8/RX_D2)
NetR118_2: R118.2 U25.13(Strap7/RX_D3)
NetR119_2: R119.2 U25.20(RX_ER/Strap6)
NetR120_2: R120.2 U25.22(TX_CLK/Strap5)
NetR121_1: R121.1 R123.2
NetR121_2: R121.2 U25.28(COL/LED_2/GPIOStrap4)
NetR122_1: R122.1 R124.2
NetR122_2: R122.2 U25.29(CRS/Strap3)
NetR125_2: R125.2 U25.30(LED0/Strap2)
NetR126_2: R126.2 U25.16(Strap0/RX_D0)
NetR132_2: R132.2 RJ1.11(LEFT_LED_CATHODE)
NetR135_2: R135.2 RJ1.1(RIGHT_LED_ANODE)
NetR143_2: R143.2 U26.10(RBias)
NetR144_1: R144.1 U26.25(TX_D1)
NetR148_2: R148.2 U26.19(RX_CLK/50MHZ_RMII)
NetR149_2: R149.2 U26.18(RX_DV/CRS_DV/Strap10)
NetR150_2: R150.2 U26.15(Strap9/RX_D1)
NetR151_1: R151.1 U26.30(LED0/Strap2)
NetR152_2: R152.2 U26.14(Strap8/RX_D2)
NetR153_2: R153.2 U26.13(Strap7/RX_D3)
NetR154_2: R154.2 U26.20(RX_ER/Strap6)
NetR155_2: R155.2 U26.22(TX_CLK/Strap5)
NetR156_1: R156.1 R159.2
NetR156_2: R156.2 U26.28(COL/LED_2/GPIOStrap4)
NetR157_1: R157.1 R160.2
NetR157_2: R157.2 U26.29(CRS/Strap3)
NetR158_2: R158.2 U26.16(Strap0/RX_D0)
NetR167_2: R167.2 RJ2.11(LEFT_LED_CATHODE)
NetR169_2: R169.2 RJ2.1(RIGHT_LED_ANODE)
NetR203_1: R203.1 U26.24(TX_D0)

Not connected (* = marked no-connect by the designer): RJ1 9(NC)*; RJ2 9(NC)*; U25 1(ModeSelect)* 8(XO)*; U26 1(ModeSelect)* 8(XO)*

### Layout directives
differential pair: PHY0_RD_N, PHY0_RD_P, PHY0_TD_N, PHY0_TD_P, PHY1_RD_N, PHY1_RD_P, PHY1_TD_N, PHY1_TD_P

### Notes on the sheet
- EtherCAT EEPROM
- (near U25) EtherCAT PHY0
- (near C87) Place near RJ1
- Place near P0
- (near C95) Place near RJ1
- (near R88) PHY0 Address selection
- PHY0_ADDR=0x0
- Run and Error LEDs
- (near R136) Place near RJ1
- EtherCAT PHY1
- (near C102) Place near RJ2
- PHY1 Address selection
- Place near P1
- (near C111) Place near RJ2
- PHY1_ADDR=0x1
- (near R170) Place near RJ2
- Refer Application Notes for PHY boot strapping configuration: https://www.ti.com/lit/an/snla344b/snla344b.pdf

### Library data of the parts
C86 C90 C98 C100 C103 C106 C114 C116 = CMP-0006228-2: as C52 on sheet MCU114E1_Power
C87 C95 C102 C111 = CMP-0006325-2: CAP, CERM, 0.1 uF, 50 V, +/- 10%, X7R, AEC-Q200 Grade 1, 0402; Manufacturer: TDK; TaMin_C: -55°C; ESR_ohm: 39.064m; Polarized: N; SizeAreaWB_mm2: 3; Value1: 0.039064 ohm; U/M: EA; Value: 0.1uF; TaMax_C: 125°C; SizeZ_mm: 0.6; SizeX_mm: 1; SizeY_mm: 0.5; Value2: 50V; AEC Qualified: Y; Cap_F: 100nF; IRMS_A: 814.669mA; AEC Category: Q200
C88 C96 C104 C112 = CMP-0086061-1: CAP, CERM, 1 µF, 25 V,+/- 10%, X5R, 0402; Manufacturer: MuRata; SizeY_mm: 0.5; TaMin_C: -55°C; VDC_V: 25V; Polarized: N; AEC Category: Q200; SizeX_mm: 1; SizeAreaWB_mm2: 3; SizeZ_mm: 0.6; Value: 1uF; TaMax_C: 85°C; U/M: EA
C89 C105 = CMP-0006283-2: CAP, CERM, 2.2 uF, 35 V, +/- 10%, X5R, 0402; Manufacturer: TDK; TaMin_C: -55°C; ESR_ohm: 5.925m; Polarized: N; SizeAreaWB_mm2: 3; Value1: 0.005925 ohm; U/M: EA; Value: 2.2uF; TaMax_C: 85°C; SizeZ_mm: 0.65; SizeX_mm: 1; SizeY_mm: 0.5; Value2: 35V; Cap_F: 2.2µF; IRMS_A: 2.0559A; AEC Category: Q200
C91-C94 C107-C110 = CMP-0096999-1: 4.7 pF ±0.5pF 50V Ceramic Capacitor C0G, NP0 0402 (1005 Metric); Manufacturer: Wurth Electronics; Value: 4.7pF; TempCo: 30ppm/°C; SizeZ_mm: 0.55mm; AEC Qualified: No
C97 C113 = CMP-0007324-5: CAP, CERM, 22 uF, 10 V, +/- 20%, X5R, 0603; Manufacturer: MuRata; TaMin_C: -55°C; Polarized: N; SizeAreaWB_mm2: 4.68; Value1: Unknown; U/M: EA; Value: 22uF; TaMax_C: 85°C; SizeZ_mm: 1; SizeX_mm: 1.6; SizeY_mm: 0.8; Value2: 10V; SizeArea_mm2: 1.28; Cap_F: 22µF; AEC Category: Q200
C99 C115 = CMP-0007313-5: CAP, CERM, 47 uF, 6.3 V, +/- 20%, X5R, 0603; Manufacturer: MuRata; TaMin_C: -55°C; Polarized: N; SizeAreaWB_mm2: 4.68; Value1: Unknown; U/M: EA; Value: 47uF; TaMax_C: 85°C; SizeZ_mm: 1; SizeX_mm: 1.6; SizeY_mm: 0.8; Value2: 6.3V; SizeArea_mm2: 1.28; Cap_F: 47µF; AEC Category: Q200
C101 C117 = CMP-0006674-2: CAP, CERM, 0.01 uF, 50 V, +/- 10%, X7R, 0402; Manufacturer: MuRata; TaMin_C: -55°C; Polarized: N; SizeAreaWB_mm2: 3; Value1: Unknown; U/M: EA; Value: 0.01uF; TaMax_C: 125°C; SizeZ_mm: 0.6; SizeX_mm: 1; SizeY_mm: 0.5; Value2: 50V; Cap_F: 10nF; AEC Category: Q200
D11 = CMP-0002951-3: LED, Red, SMD; Manufacturer: Wurth Elektronik; Type: AlInGaP; Vf_V: 1.9V; Io_A: 30mA; Vr_V: 5V; Ir_A: 25µA; Tjmax_C: 85°C; Power_TotalModule: 72mW; Value1: 0.072W; Angle: 140
D12 = CMP-0002960-2: as D9 on sheet MCU114E1_Power
R32 R105 R106 R108 R141 R142 = CMP-0026631-1: RES, 4.70 k, 1%, 0.063 W, 0402; Manufacturer: TE Connectivity; Power_W: 63mW; TempCo: 100 ppm/C; Value_Code: 4k70; U/M: EA; Value: 4.70k; Res_ohm: 4.7k; SizeX_mm: 1; SizeY_mm: 0.5; SizeZ_mm: 0.6; Value2: 0.063W; AEC Qualified: N; AEC Category: Q200
R58 R83 R84 R86 R87 R91 R92 R110 R144 R203 = CMP-0081856-1: as R2 on sheet MCU114E1_Power
R88 R89 R111-R113 R127-R130 R133 R145-R147 R161-R163 = CMP-0026237-2: RES, 2.49 k, 1%, 0.063 W, AEC-Q200 Grade 0, 0402; Manufacturer: Vishay-Dale; Power_W: 63mW; TempCo: 100 ppm/C; Value_Code: 2k49; Value: 2.49k; EIA_Code: E96; SizeX_mm: 1; SizeY_mm: 0.5; SizeZ_mm: 0.6; Value2: 0.063W; AEC Qualified: Y; VDC_V: 50V; AEC Category: Q200; AEC Grade: 0
R107 R123-R125 R151 R159 R160 = CMP-0026231-2: RES, 2.20 k, 1%, 0.063 W, AEC-Q200 Grade 0, 0402; Manufacturer: Vishay-Dale; Power_W: 63mW; TempCo: 100 ppm/C; Value_Code: 2k20; Value: 2.20k; Res_ohm: 2.2k; SizeX_mm: 1; SizeY_mm: 0.5; SizeZ_mm: 0.6; Value2: 0.063W; AEC Qualified: Y; AEC Category: Q200; AEC Grade: 0
R109 R143 = CMP-0026515-2: RES, 6.49 k, 1%, 0.063 W, AEC-Q200 Grade 0, 0402; Manufacturer: Vishay-Dale; Power_W: 63mW; TempCo: 100 ppm/C; Value_Code: 6k49; Value: 6.49k; EIA_Code: E96; SizeX_mm: 1; SizeY_mm: 0.5; SizeZ_mm: 0.6; Value2: 0.063W; AEC Qualified: Y; VDC_V: 50V; AEC Category: Q200; AEC Grade: 0
R114-R122 R126 R148-R150 R152-R158 = CMP-0026299-2: RES, 33.2, 1%, 0.063 W, AEC-Q200 Grade 0, 0402; Manufacturer: Vishay-Dale; Power_W: 63mW; TempCo: 100 ppm/C; Value_Code: 33R2; Value: 33.2; EIA_Code: E96; SizeX_mm: 1; SizeY_mm: 0.5; SizeZ_mm: 0.6; Value2: 0.063W; AEC Qualified: Y; VDC_V: 50V; AEC Category: Q200; AEC Grade: 0
R131 R134 R166 R168 = CMP-0086542-2: RMCF/RMCP Series General Purpose Thick Film Standard Power and High Power Chip Resistor; Manufacturer: Stackpole
R132 R135 R167 R169 = CMP-0025813-4: RES, 470, 5%, 0.1 W, AEC-Q200 Grade 0, 0603; Manufacturer: Vishay-Dale; Power_W: 100mW; TempCo: 200 ppm/C; Value_Code: 470R; Value: 470; EIA_Code: E24; SizeX_mm: 1.6; SizeY_mm: 0.8; SizeZ_mm: 1; Value2: 0.1W; SizeArea_mm2: 1.28; AEC Qualified: Y; VDC_V: 75V; AEC Category: Q200; AEC Grade: 0
R136 R170 = CMP-0026757-1: RES, 1.00 M, 1%, 0.063 W, AEC-Q200 Grade 0, 0402; Manufacturer: Stackpole Electronics Inc; Power_W: 63mW; TempCo: 100 ppm/C; Value_Code: 1M00; U/M: EA; Value: 1.00Meg; EIA_Code: E96; Res_ohm: 1M; SizeX_mm: 1; SizeY_mm: 0.5; SizeZ_mm: 0.6; Value2: 0.063W; AEC Qualified: Y; VDC_V: 50V; AEC Grade: 0; AEC Category: Q200
R137 = CMP-0026081-3: RES, 1.27 k, 1%, 0.063 W, AEC-Q200 Grade 0, 0402; Manufacturer: Vishay-Dale; Power_W: 63mW; TempCo: 100 ppm/C; Value_Code: 1k27; Value: 1.27k; EIA_Code: E96; SizeX_mm: 1; SizeY_mm: 0.5; SizeZ_mm: 0.6; Value2: 0.063W; AEC Qualified: Y; VDC_V: 50V; AEC Category: Q200; AEC Grade: 0
R138 = CMP-0026962-3: RES, 680, 5%, 0.063 W, AEC-Q200 Grade 0, 0402; Manufacturer: Vishay-Dale; Value: 680; Value_Code: 680R; Power_W: 63mW; Value2: 0.063W; VDC_V: 50V; TempCo: 200 ppm/C; EIA_Code: E24; AEC Category: Q200; AEC Qualified: Y; AEC Grade: 0; SizeArea_mm2: 0.5; SizeX_mm: 1; SizeZ_mm: 0.6
R139 R140 = CMP-0026863-2: RES, 1.5 M, 5%, 0.063 W, AEC-Q200 Grade 0, 0402; Manufacturer: Vishay-Dale; Power_W: 63mW; TempCo: 200 ppm/C; Value_Code: 1M50; Value: 1.5Meg; EIA_Code: E24; SizeX_mm: 1; SizeY_mm: 0.5; SizeZ_mm: 0.6; Value2: 0.063W; AEC Qualified: Y; VDC_V: 50V; AEC Category: Q200; AEC Grade: 0
RJ1 RJ2 = CMP-0086350-1: Connector, RJ45, 1x1, Gold, R/A, SMT; Manufacturer: Wurth Elektronik; Row_Count: 1; Gender: Female
U16 = CMP-0082059-1: 16 Kb I2C EEPROM Serial, SOIC-8; Manufacturer: ON Semiconductor; SizeArea_mm2: 29.351; SizeAreaWB_mm2: 55.131; SizeY_mm: 4.9; SizeZ_mm: 1.75; SizeX_mm: 5.99
U17 U19 = CMP-0073613-3: 4-Channel Ultra-Low-Capacitance IEC ESD Protection Diode, DQA0010A (USON-10); Alternate Manufacturer: Texas Instruments; Green_Lifecycle: Active; SizeAreaWB_mm2: 7.0; Green_REACh: Passed; SizeZ_mm: 0.55; SizeX_mm: 1.0; SizeY_mm: 2.5; CompType: IC; AEC Category: Q200; AEC Qualified: N
U18 = CMP-0051777-2: Dual Inverter Buffer/Driver with Open-Drain Output, DBV0006A, LARGE T&R; Manufacturer: Texas Instruments; Schmitt Trigger: No; Logic: Inverting; F @ Nom Voltage(Max)(Mhz): 150; VCC(Max)(V): 5.5; Rating: Catalog; Sub-Family: Inverting Buffer/Driver; Technology Family: LVC; VCC(Min)(V): 1.65; Voltage(Nom)(V): 1.8,2.5,3.3,5; Output Drive (IOL/IOH)(Max)(mA): 32/-32; Output Type: CMOS; ICC @ Nom Voltage(Max)(mA): 0.01; Bits(#): 2; tpd @ Nom Voltage(Max)(ns): 8.2,4.4,3.9,3.4; Input Type: CMOS/TTL
U25 U26 = CMP-0860427-2: DP83826ERHB, RHB0032M (VQFN-32); Alternate Manufacturer: Texas Instruments; AEC Category: Q200; SizeArea_mm2: 25; SizeAreaWB_mm2: 49; AEC Qualified: N; CompType: IC; SizeY_mm: 5; SizeZ_mm: 1

## Sheet MCU114E1_USB.SchDoc
size 431 x 279 mm; Date: Not shown in title block; ApprovedBy: Not shown in title block; CheckedBy: Not shown in title block; Author: Not shown in title block; CompanyName: Not shown in title block; Engineer: Not shown in title block; Organization: Not shown in title block; Address1: Not shown in title block; Address2: Not shown in title block; Address3: Not shown in title block; Address4: Not shown in title block; DocumentNumber: 7; Revision: Use project parameter SCH_Rev; SheetNumber: 7; SheetTotal: 11; PageSetup: Record=PageOptions¦CenterHorizontal=True¦CenterVertical=True¦PrintScale=1.00¦XCorrection=1.00¦YCorrection=1.00¦PrintKind=0¦BorderSize=5000000¦LeftOffset=0¦BottomOffset=0¦Orientation=2¦PaperLength=1000¦PaperWidth=1000¦Scale=100¦PaperSource=15¦PrintQuality=600¦MediaType=1¦DitherType=10¦PaperKind=Letter¦PrintScaleMode=1

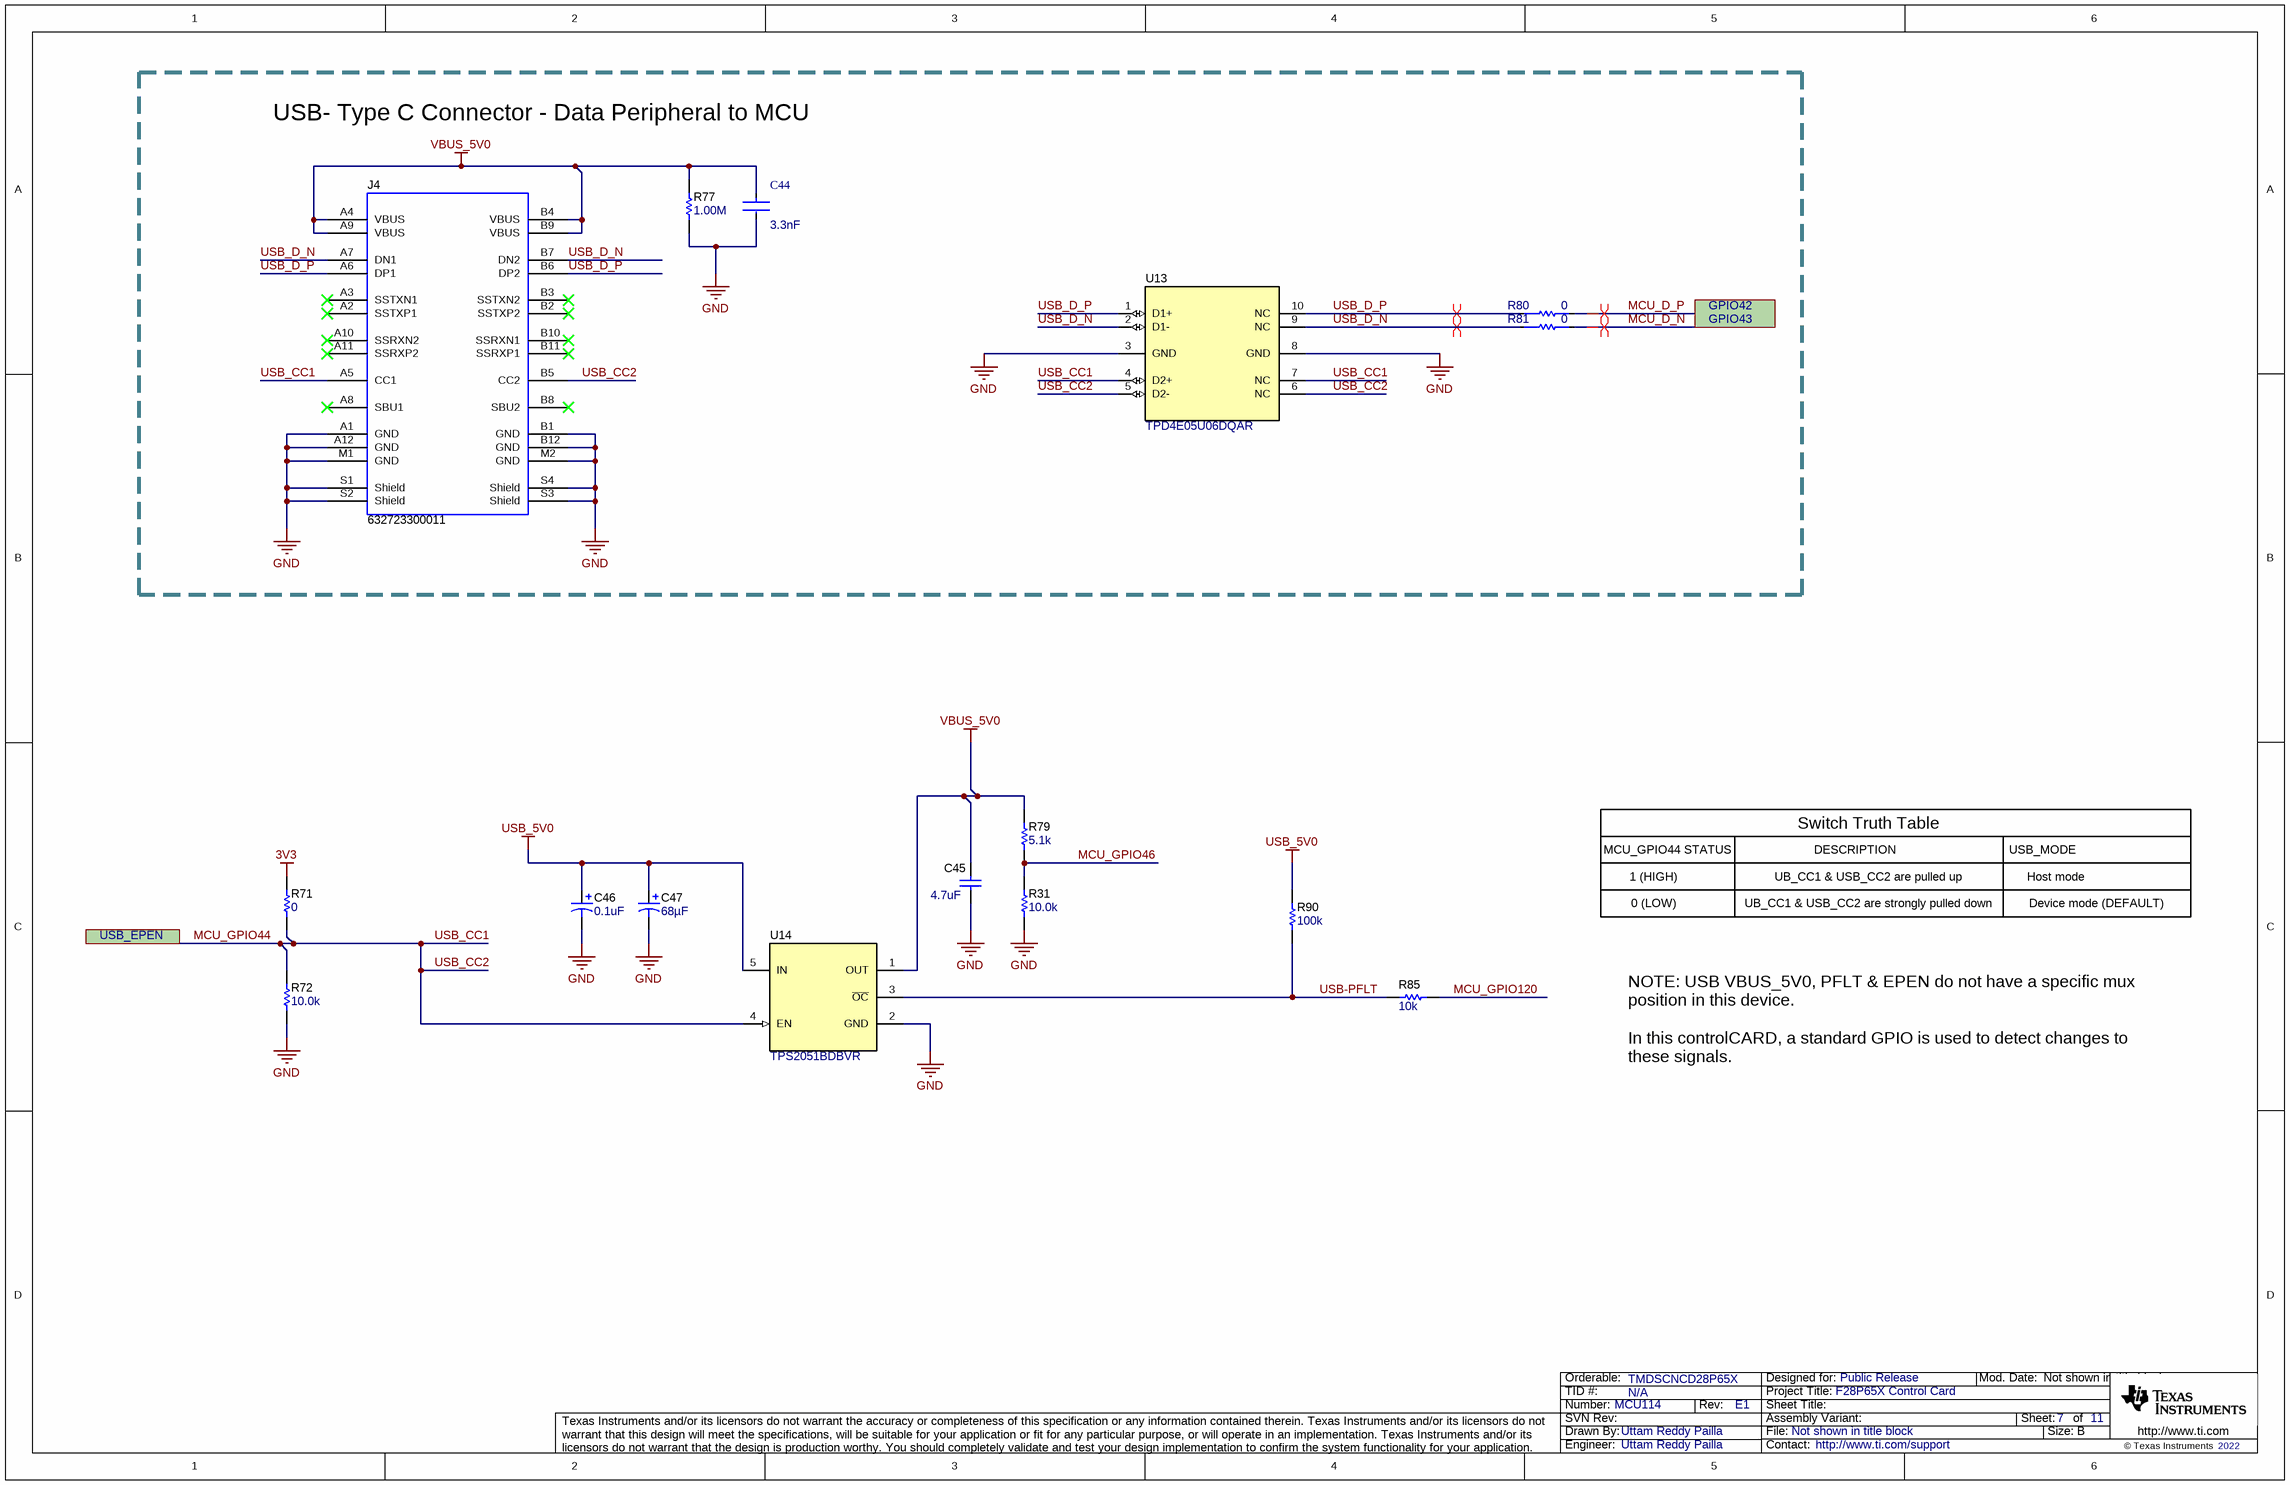
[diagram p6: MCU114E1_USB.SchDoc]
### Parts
C44  Capacitance: 3.3nF  [FP-CL388-IPC_C]  (hidden comment: CL05B332KB5NNNC)
C45  ValueDisplayed: 4.7uF  [0603]  (hidden comment: C0603C475K8PACTU)
C46  ValueDisplayed: 0.1uF  [3216-18]  (hidden comment: 293D104X9035A2TE3)
C47  ValueDisplayed: 68µF  [3216-18]  (hidden comment: TLJA686M010R1500)
J4  632723300011  [Wurth_632_723_300_011]
R31  ValueDisplayed: 10.0k  [0402]  (hidden comment: AC0402FR-0710KL)
R71  ValueDisplayed: 0  [0402]  (hidden comment: CRCW04020000Z0EDHP)
R72  ValueDisplayed: 10.0k  [0402]  (hidden comment: AC0402FR-0710KL)
R77  ValueDisplayed: 1.00M  [0402]  (hidden comment: RMCF0402FT1M00)
R79  ValueDisplayed: 5.1k  [0603]  (hidden comment: RC0603JR-075K1L)
R80  0  [FP-CRCW04020000Z0EDC_0402-MFG]
R81  0  [FP-CRCW04020000Z0EDC_0402-MFG]
R85  ValueDisplayed: 10k  [0805_HV]  (hidden comment: ERJ-6GEYJ103V)
R90  ValueDisplayed: 100k  [0603]  (hidden comment: CRCW0603100KJNEA)
U13  TPD4E05U06DQAR  [DQA0010A]
U14  TPS2051BDBVR  [DBV0005A_N]

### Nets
3V3: R71.2
GND: C44.2 C45.2 C46.2(-) C47.2(-) J4.A1(GND) J4.A12(GND) J4.B1(GND) J4.B12(GND) J4.M1(GND) J4.M2(GND) J4.S1(Shield) J4.S2(Shield) J4.S3(Shield) J4.S4(Shield) R31.1 R72.1 R77.1 U13.3(GND) U13.8(GND) U14.2(GND)
USB_5V0: C46.1(+) C47.1(+) R90.2 U14.5(IN)
VBUS_5V0: C44.1 C45.1 J4.A4(VBUS) J4.A9(VBUS) J4.B4(VBUS) J4.B9(VBUS) R77.2 R79.2 U14.1(OUT)
MCU_D_N: R81.2
MCU_D_P: R80.2
MCU_GPIO44: J4.A5(CC1) J4.B5(CC2) R71.1 R72.2 U13.4(D2+) U13.5(D2-) U13.6(NC) U13.7(NC) U14.4(EN)  [also labelled USB_CC1, USB_CC2]
MCU_GPIO46: R31.2 R79.1
MCU_GPIO120: R85.2
USB-PFLT: R85.1 R90.1 U14.3(~{OC})
USB_D_N: J4.A7(DN1) J4.B7(DN2) R81.1 U13.2(D1-) U13.9(NC)
USB_D_P: J4.A6(DP1) J4.B6(DP2) R80.1 U13.1(D1+) U13.10(NC)

Not connected (* = marked no-connect by the designer): J4 A2(SSTXP1)* A3(SSTXN1)* A8(SBU1)* A10(SSRXN2)* A11(SSRXP2)* B2(SSTXP2)* B3(SSTXN2)* B8(SBU2)* B10(SSRXN1)* B11(SSRXP1)*

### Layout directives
differential pair: MCU_D_N, MCU_D_P, USB_D_N, USB_D_P

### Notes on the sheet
- USB- Type C Connector - Data Peripheral to MCU
- GPIO42
- GPIO43
- Switch Truth Table
- 0 (LOW)
- 1 (HIGH)
- MCU_GPIO44 STATUS
- DESCRIPTION
- UB_CC1 & USB_CC2 are pulled up
- UB_CC1 & USB_CC2 are strongly pulled down
- USB_MODE
- Host mode
- Device mode (DEFAULT)
- USB_EPEN
- NOTE: USB VBUS_5V0, PFLT & EPEN do not have a specific mux position in this device.
  In this controlCARD, a standard GPIO is used to detect changes to these signals.

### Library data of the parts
C44 = CMP-13271-000627-1: Cap Ceramic 3.3nF 50V X7R ±10% SMD 0402 +125°C Paper T/R
C45 = CMP-0006949-5: CAP, CERM, 4.7 uF, 10 V, +/- 10%, X5R, 0603; Manufacturer: Kemet; TaMin_C: -55°C; ESR_ohm: 6m; Polarized: N; SizeAreaWB_mm2: 4.68; Value1: 0.006 ohm; U/M: EA; Value: 4.7uF; TaMax_C: 85°C; SizeZ_mm: 1; SizeX_mm: 1.6; SizeY_mm: 0.8; Value2: 10V; SizeArea_mm2: 1.28; Cap_F: 4.7µF; IRMS_A: 7.24A; AEC Category: Q200
C46 = CMP-0011440-2: CAP, TA, 0.1 uF, 35 V, +/- 10%, 20 ohm, SMD; Manufacturer: Vishay-Sprague; TaMin_C: -55°C; ESR_ohm: 20; Polarized: Y; SizeAreaWB_mm2: 10.92; Value1: 20 ohm; U/M: EA; Value: 0.1uF; TaMax_C: 125°C; SizeZ_mm: 1.8; SizeX_mm: 3.2; SizeY_mm: 1.6; Cap_Case: A; Value2: 35V; SizeArea_mm2: 5.12; CompType: Capacitor; Cap_F: 100nF; IRMS_A: 60mA; AEC Category: Q200
C47 = CMP-0081926-1: CAP, TA, 68 µF, 10 V, +/- 20%, 1.5 ohm, SMD; Manufacturer: AVX; TaMin_C: -55°C; ESR_ohm: 1.5; Polarized: Y; SizeAreaWB_mm2: 10.92; Value1: 1.5 ohm; Value: 68uF; TaMax_C: 125°C; SizeZ_mm: 1.8; SizeX_mm: 3.2; SizeY_mm: 1.6; Value2: 10V; SizeArea_mm2: 5.12; CompType: Capacitor; AEC Qualified: N; IRMS_A: 224mA; AEC Category: Q200
J4 = CMP-0080891-1: Connector, Receptacle, USB Type C, R/A; Manufacturer: Wurth Elektronik; Current_A: 3A; Gender: Female; Voltage_V: 5V; ContactFinish: Gold; Cert_UL: Y
R31 R72 = CMP-0077731-1: as R103 on sheet MCU114E1_Power
R71 = CMP-0081856-1: as R2 on sheet MCU114E1_Power
R77 = CMP-0026757-1: as R136 on sheet MCU114E1_EtherCAT
R79 = CMP-0025932-5: RES, 5.1 k, 5%, 0.1 W, 0603; Manufacturer: Yageo; Power_W: 100mW; TempCo: 100 ppm/C; Value_Code: 5k10; Value: 5.1k; EIA_Code: E24; SizeX_mm: 1.6; SizeY_mm: 0.8; SizeZ_mm: 1; Value2: 0.1W; SizeArea_mm2: 1.28; AEC Qualified: N; VDC_V: 75V; AEC Category: Q200; SizeAreaWB_mm2: 4.68
R80 R81 = CMP-0093210-1: as R97 on sheet MCU114E1_Power
R85 = CMP-0020620-3: RES, 10 k, 5%, 0.125 W, AEC-Q200 Grade 0, 0805; Manufacturer: Panasonic; Power_W: 125mW; TempCo: 200 ppm/C; Value_Code: 10k0; Value: 10k; EIA_Code: E24; SizeX_mm: 2; SizeY_mm: 1.25; SizeZ_mm: 1.45; Value2: 0.125W; SizeArea_mm2: 2.5; AEC Qualified: Y; VDC_V: 150V; AEC Category: Q200; AEC Grade: 0; SizeAreaWB_mm2: 6.75
R90 = CMP-0025698-4: as R53 on sheet MCU114E1_Power
U13 = CMP-0073613-3: as U17 on sheet MCU114E1_EtherCAT
U14 = CMP-0074276-1: Single, Current-Limited, Power-Distribution Switch, DBV0005A (SOT-23-5); Alternate PartNumber: TPS2051BDBVT; Alternate Manufacturer: Texas Instruments; Green_Lifecycle: Active; SizeAreaWB_mm2: 14.82; Green_REACh: Passed; U/M: EA; SizeZ_mm: 1.45; SizeX_mm: 2.8; SizeY_mm: 2.9; SizeArea_mm2: 8.12; CompType: IC

## Sheet MCU114E1_XDS110_USB_Power.SchDoc
size 431 x 279 mm; Date: Not shown in title block; ApprovedBy: Not shown in title block; CheckedBy: Not shown in title block; Author: Not shown in title block; CompanyName: Not shown in title block; Engineer: Not shown in title block; Organization: Not shown in title block; Address1: Not shown in title block; Address2: Not shown in title block; Address3: Not shown in title block; Address4: Not shown in title block; DocumentNumber: 8; Revision: Use project parameter SCH_Rev; SheetNumber: 8; SheetTotal: 11; PageSetup: Record=PageOptions¦CenterHorizontal=True¦CenterVertical=True¦PrintScale=1.00¦XCorrection=1.00¦YCorrection=1.00¦PrintKind=0¦BorderSize=5000000¦LeftOffset=0¦BottomOffset=0¦Orientation=2¦PaperLength=1000¦PaperWidth=1000¦Scale=100¦PaperSource=15¦PrintQuality=600¦MediaType=1¦DitherType=10¦PaperKind=Letter¦PrintScaleMode=1

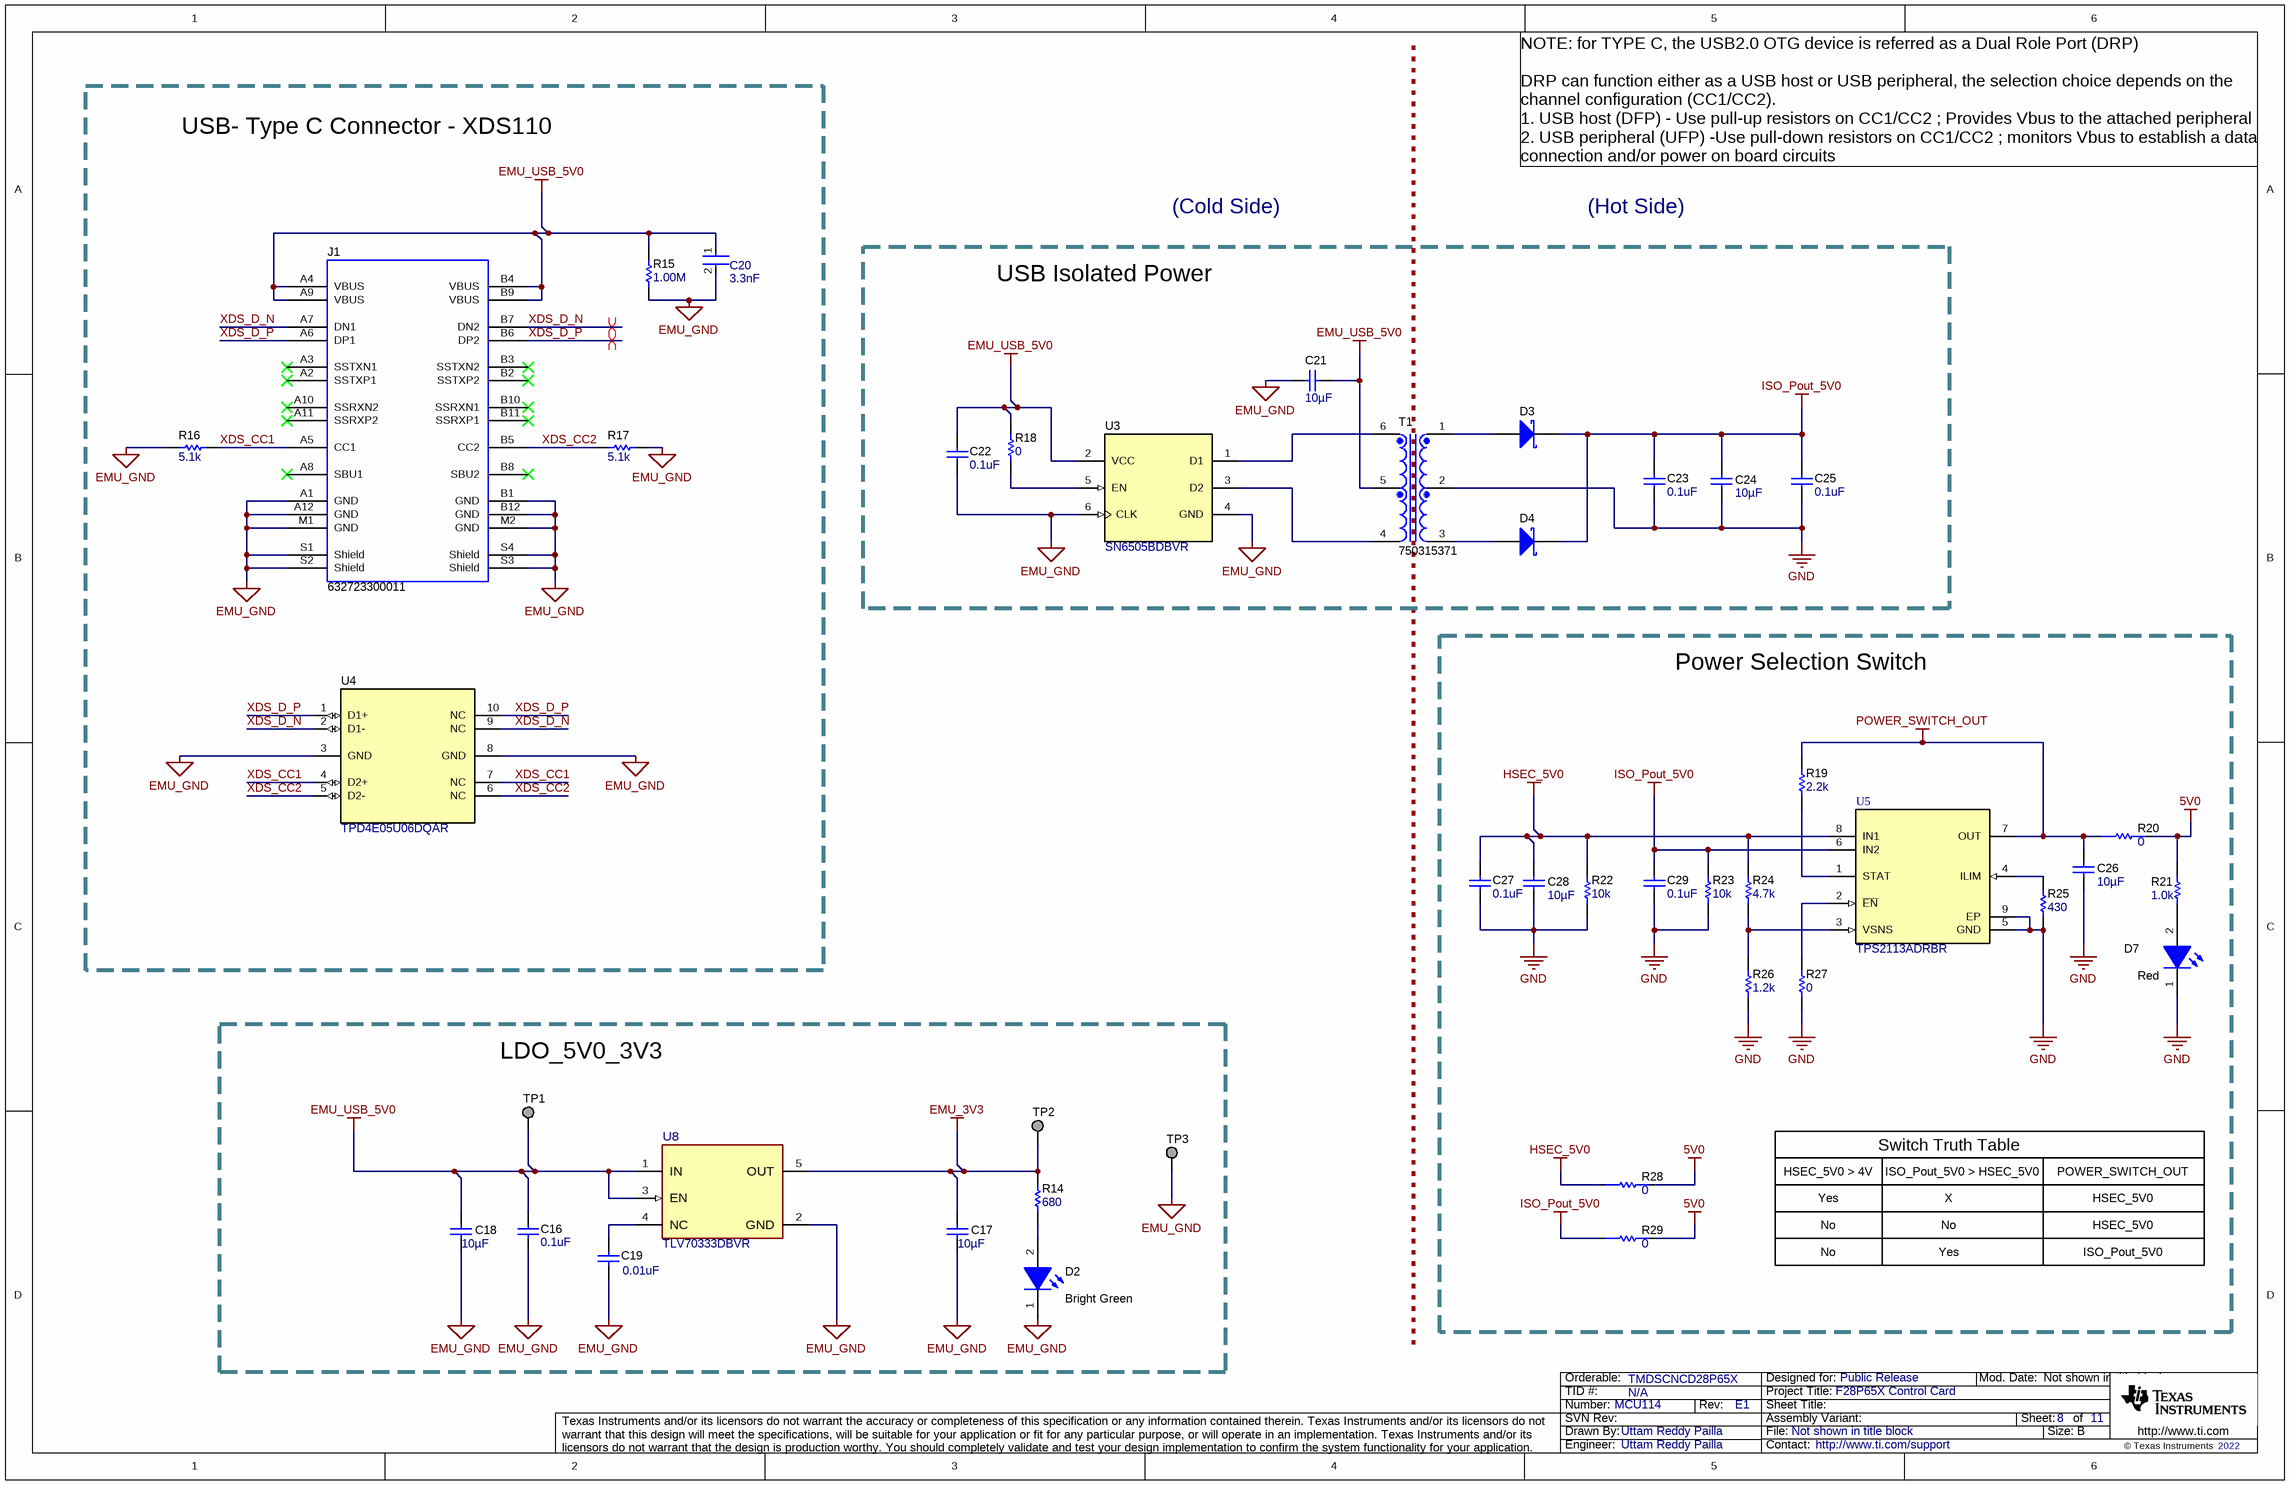
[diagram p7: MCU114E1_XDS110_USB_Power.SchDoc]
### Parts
C16  ValueDisplayed: 0.1uF  [0402]  (hidden comment: 885012205037)
C17  ValueDisplayed: 10µF  [0402_080]  (hidden comment: 0402ZD106MAT2A)
C18  ValueDisplayed: 10µF  [0402_080]  (hidden comment: 0402ZD106MAT2A)
C19  ValueDisplayed: 0.01uF  [0402]  (hidden comment: 885012205031)
C20  Capacitance: 3.3nF  [FP-CL388-IPC_C]  (hidden comment: CL05B332KB5NNNC)
C21  ValueDisplayed: 10µF  [0603]  (hidden comment: GRM188R61C106KAALD)
C22  ValueDisplayed: 0.1uF  [0402]  (hidden comment: 885012205037)
C23  ValueDisplayed: 0.1uF  [0402]  (hidden comment: 885012205037)
C24  ValueDisplayed: 10µF  [0603]  (hidden comment: GRM188R61C106KAALD)
C25  ValueDisplayed: 0.1uF  [0402]  (hidden comment: 885012205037)
C26  ValueDisplayed: 10µF  [0603]  (hidden comment: GRM188R61C106KAALD)
C27  ValueDisplayed: 0.1uF  [0402]  (hidden comment: 885012205037)
C28  ValueDisplayed: 10µF  [0603]  (hidden comment: GRM188R61C106KAALD)
C29  ValueDisplayed: 0.1uF  [0402]  (hidden comment: 885012205037)
D2  value Bright Green  [WL-SMCW_Green_0805]  (hidden comment: 150080VS75000)
D3  1N5819HW-7-F  [SOD-123]  (value not drawn)
D4  1N5819HW-7-F  [SOD-123]  (value not drawn)
D7  value Red  [WL-SMCW_RED_0805]  (hidden comment: 150080SS75000)
J1  632723300011  [Wurth_632_723_300_011]
R14  ValueDisplayed: 680  [0402]  (hidden comment: CRCW0402680RJNED)
R15  ValueDisplayed: 1.00M  [0402]  (hidden comment: RMCF0402FT1M00)
R16  ValueDisplayed: 5.1k  [0603]  (hidden comment: RC0603JR-075K1L)
R17  ValueDisplayed: 5.1k  [0603]  (hidden comment: RC0603JR-075K1L)
R18  ValueDisplayed: 0  [0603]  (hidden comment: ERJ-3GEY0R00V)
R19  ValueDisplayed: 2.2k  [0603]  (hidden comment: CRCW06032K20JNEA)
R20  0  [FP-MCT0603MZ0000ZP500_0603-MFG]
R21  ValueDisplayed: 1.0k  [0603]  (hidden comment: RCA06031K00JNEA)
R22  ValueDisplayed: 10k  [0603]  (hidden comment: CRCW060310K0JNEA)
R23  ValueDisplayed: 10k  [0603]  (hidden comment: CRCW060310K0JNEA)
R24  ValueDisplayed: 4.7k  [0603]  (hidden comment: RC0603JR-074K7L)
R25  ValueDisplayed: 430  [0603]  (hidden comment: RC0603FR-07430RL)
R26  ValueDisplayed: 1.2k  [0603]  (hidden comment: RC0603JR-071K2L)
R27  ValueDisplayed: 0  [0603]  (hidden comment: ERJ-3GEY0R00V)
R28  0  [FP-MCT0603MZ0000ZP500_0603-MFG]
R29  0  [FP-MCT0603MZ0000ZP500_0603-MFG]
T1  750315371  [Wurth_750315371]
TP1  TESTPOINT  [TP_50MIL-25MILHOLE]  (value not drawn)  (no BOM)
TP2  TESTPOINT  [TP_50MIL-25MILHOLE]  (value not drawn)  (no BOM)
TP3  TESTPOINT  [TP_50MIL-25MILHOLE]  (value not drawn)  (no BOM)
U3  SN6505BDBVR  [DBV0006A_L]
U4  TPD4E05U06DQAR  [DQA0010A]
U5  TPS2113ADRBR  [DRB0008B]
U8  TLV70333DBVR  [DBV0005A-MFG]

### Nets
5V0: R20.2 R21.2 R28.2 R29.2
EMU_3V3: C17.1 R14.1 TP2.1 U8.5(OUT)
EMU_GND: C16.2 C17.2 C18.2 C19.2 C20.2 C21.1 C22.2 D2.1(K) J1.A1(GND) J1.A12(GND) J1.B1(GND) J1.B12(GND) J1.M1(GND) J1.M2(GND) J1.S1(Shield) J1.S2(Shield) J1.S3(Shield) J1.S4(Shield) R15.1 R16.1 R17.2 TP3.1 U3.4(GND) U3.6(CLK) U4.3(GND) U4.8(GND) U8.2(GND)
EMU_USB_5V0: C16.1 C18.1 C20.1 C21.2 C22.1 J1.A4(VBUS) J1.A9(VBUS) J1.B4(VBUS) J1.B9(VBUS) R15.2 R18.2 T1.5 TP1.1 U3.2(VCC) U8.1(IN) U8.3(EN)
GND: C23.2 C24.2 C25.2 C26.2 C27.2 C28.2 C29.2 D7.1(K) R22.1 R23.1 R25.1 R26.1 R27.1 T1.2 U5.5(GND) U5.9(EP)
HSEC_5V0: C27.1 C28.1 R22.2 R24.2 R28.1 U5.8(IN1)
ISO_Pout_5V0: C23.1 C24.1 C25.1 C29.1 D3.1(K) D4.1(K) R23.2 R29.1 U5.6(IN2)
POWER_SWITCH_OUT: C26.1 R19.2 R20.1 U5.7(OUT)
XDS_CC1: J1.A5(CC1) R16.2 U4.4(D2+) U4.7(NC)
XDS_CC2: J1.B5(CC2) R17.1 U4.5(D2-) U4.6(NC)
XDS_D_N: J1.A7(DN1) J1.B7(DN2) U4.2(D1-) U4.9(NC)
XDS_D_P: J1.A6(DP1) J1.B6(DP2) U4.1(D1+) U4.10(NC)
NetC19_1: C19.1 U8.4(NC)
NetD2_2: D2.2(A) R14.2
NetD3_2: D3.2(A) T1.1
NetD4_2: D4.2(A) T1.3
NetD7_2: D7.2(A) R21.1
NetR18_1: R18.1 U3.5(EN)
NetR19_1: R19.1 U5.1(STAT)
NetR24_1: R24.1 R26.2 U5.3(VSNS)
NetR25_2: R25.2 U5.4(ILIM)
NetR27_2: R27.2 U5.2(~{EN})
NetT1_4: T1.4 U3.3(D2)
NetT1_6: T1.6 U3.1(D1)

Not connected (* = marked no-connect by the designer): J1 A2(SSTXP1)* A3(SSTXN1)* A8(SBU1)* A10(SSRXN2)* A11(SSRXP2)* B2(SSTXP2)* B3(SSTXN2)* B8(SBU2)* B10(SSRXN1)* B11(SSRXP1)*

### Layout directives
differential pair: XDS_D_N, XDS_D_P

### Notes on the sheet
- USB- Type C Connector - XDS110
- NOTE: for TYPE C, the USB2.0 OTG device is referred as a Dual Role Port (DRP)
  DRP can function either as a USB host or USB peripheral, the selection choice depends on the channel configuration (CC1/CC2).
  1. USB host (DFP) - Use pull-up resistors on CC1/CC2 ; Provides Vbus to the attached peripheral
  2. USB peripheral (UFP) -Use pull-down resistors on CC1/CC2 ; monitors Vbus to establish a data connection and/or power on board circuits
- (Cold Side)
- (Hot Side)
- USB Isolated Power
- Power Selection Switch
- LDO_5V0_3V3
- HSEC_5V0 > 4V
- Switch Truth Table
- ISO_Pout_5V0 > HSEC_5V0
- POWER_SWITCH_OUT
- Yes
- No
- X
- HSEC_5V0
- ISO_Pout_5V0

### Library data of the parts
C16 C22 C23 C25 C27 C29 = CMP-0006228-2: as C52 on sheet MCU114E1_Power
C17 C18 = CMP-0078623-1: CAP, CERM, 10 µF, 10 V,+/- 20%, X5R, 0402; Manufacturer: AVX; SizeAreaWB_mm2: 3; SizeArea_mm2: 0.5; AEC Qualified: N; AEC Category: Q200; Value: 10uF; TaMax_C: 85°C; SizeZ_mm: 0.8; TaMin_C: -55°C; VDC_V: 10V; U/M: EA; SizeX_mm: 1
C19 = CMP-0006227-2: CAP, CERM, 0.01 uF, 16 V, +/- 10%, X7R, 0402; Manufacturer: Wurth Elektronik; TaMin_C: -55°C; Polarized: N; SizeAreaWB_mm2: 3; Value1: Unknown; U/M: EA; Value: 0.01uF; TaMax_C: 125°C; SizeZ_mm: 0.6; SizeX_mm: 1; SizeY_mm: 0.5; Value2: 16V; Cap_F: 10nF; AEC Category: Q200
C20 = CMP-13271-000627-1: as C44 on sheet MCU114E1_USB
C21 C24 C26 C28 = CMP-0086225-1: as C53 on sheet MCU114E1_Power
D2 = CMP-0002960-2: as D9 on sheet MCU114E1_Power
D3 D4 = CMP-0028360-2: Diode, Schottky, 40 V, 1 A, SOD-123; Manufacturer: Diodes Inc.; Green_Lifecycle: Active; AEC Category: Q101; TJmax_C: 125°C; SizeArea_mm2: 6.545; Vr_V: 40V; Value1: 1A; SizeZ_mm: 1.35; Value: 40V; Vf_V: 450mV; SizeX_mm: 3.85; Green_REACh: Passed; Value2: 0.45V; SizeY_mm: 1.7; SizeAreaWB_mm2: 13.095
D7 = CMP-0002951-3: LED, Red, SMD; Manufacturer: Wurth Elektronik; Type: AlInGaP; Angle: 140; Vr_V: 5V; Ir_A: 25µA; Vf_V: 1.9V; Value1: 0.072W; Tjmax_C: 85°C; Io_A: 30mA; Power_TotalModule: 72mW
J1 = CMP-0080891-1: as J4 on sheet MCU114E1_USB
R14 = CMP-0026962-3: as R138 on sheet MCU114E1_EtherCAT
R15 = CMP-0026757-1: as R136 on sheet MCU114E1_EtherCAT
R16 R17 = CMP-0025932-5: as R79 on sheet MCU114E1_USB
R18 R27 = CMP-0025874-4: RES, 0, 5%, 0.1 W, AEC-Q200 Grade 0, 0603; Manufacturer: Panasonic; Power_W: 100mW; TempCo: 600 ppm/C; Value_Code: 0000; Value: 0; EIA_Code: E24; SizeX_mm: 1.6; SizeY_mm: 0.8; SizeZ_mm: 1; Value2: 0.1W; SizeArea_mm2: 1.28; AEC Qualified: Y; VDC_V: 50V; AEC Category: Q200; SizeAreaWB_mm2: 4.68
R19 = CMP-0025769-4: RES, 2.2 k, 5%, 0.1 W, AEC-Q200 Grade 0, 0603; Manufacturer: Vishay-Dale; Power_W: 100mW; TempCo: 200 ppm/C; Value_Code: 2k20; Value: 2.2k; EIA_Code: E24; SizeX_mm: 1.6; SizeY_mm: 0.8; SizeZ_mm: 1; Value2: 0.1W; SizeArea_mm2: 1.28; AEC Qualified: Y; VDC_V: 75V; AEC Category: Q200; AEC Grade: 0
R20 R28 R29 = CMP-0096493-1: 15; Manufacturer: Vishay; Part Number: MCT0603MZ0000ZP500; VDC_V: 75V; Power_W: 150mW; AEC Qualified: Yes; SizeZ_mm: 0.55mm
R21 = CMP-0025946-3: RES, 1.0 k, 5%, 0.1 W, AEC-Q200 Grade 0, 0603; Manufacturer: Vishay-Dale; Power_W: 100mW; TempCo: 200 ppm/C; Value_Code: 1k00; U/M: EA; Value: 1.0k; EIA_Code: E24; Res_ohm: 1k; SizeX_mm: 1.6; SizeY_mm: 0.8; SizeZ_mm: 1; Value2: 0.1W; SizeArea_mm2: 1.28; AEC Qualified: Y; VDC_V: 75V; AEC Grade: 0; AEC Category: Q200
R22 R23 = CMP-0025701-4: RES, 10 k, 5%, 0.1 W, AEC-Q200 Grade 0, 0603; Manufacturer: Vishay-Dale; Power_W: 100mW; TempCo: 200 ppm/C; Value_Code: 10k0; Value: 10k; EIA_Code: E24; SizeX_mm: 1.6; SizeY_mm: 0.8; SizeZ_mm: 1; Value2: 0.1W; SizeArea_mm2: 1.28; AEC Qualified: Y; VDC_V: 75V; AEC Category: Q200; AEC Grade: 0
R24 = CMP-0025927-5: RES, 4.7 k, 5%, 0.1 W, 0603; Manufacturer: Yageo; Power_W: 100mW; TempCo: 100 ppm/C; Value_Code: 4k70; Value: 4.7k; EIA_Code: E24; SizeX_mm: 1.6; SizeY_mm: 0.8; SizeZ_mm: 1; Value2: 0.1W; SizeArea_mm2: 1.28; AEC Qualified: N; VDC_V: 75V; AEC Category: Q200; SizeAreaWB_mm2: 4.68
R25 = CMP-0023109-5: RES, 430, 1%, 0.1 W, 0603; Manufacturer: Yageo; Power_W: 100mW; TempCo: 100 ppm/C; Value_Code: 430R; Value: 430; SizeX_mm: 1.6; SizeY_mm: 0.8; SizeZ_mm: 1; Value2: 0.1W; SizeArea_mm2: 1.28; AEC Qualified: N; VDC_V: 75V; AEC Category: Q200; SizeAreaWB_mm2: 4.68
R26 = CMP-0025894-5: RES, 1.2 k, 5%, 0.1 W, 0603; Manufacturer: Yageo; Power_W: 100mW; TempCo: 100 ppm/C; Value_Code: 1k20; Value: 1.2k; EIA_Code: E24; SizeX_mm: 1.6; SizeY_mm: 0.8; SizeZ_mm: 1; Value2: 0.1W; SizeArea_mm2: 1.28; AEC Qualified: N; VDC_V: 75V; AEC Category: Q200; SizeAreaWB_mm2: 4.68
T1 = CMP-0030623-1: Transformer, 105uH, TH; Manufacturer: Wurth Elektronik; Green_Lifecycle: Active; DCR_ohm: 60m; Green_REACh: Passed; Lp: 105; Ns1toNp: 1.1; Ind_H: 105µH
TP1-TP3 = CMP-0078143-3: TEST POINT.  No entry in BOM.
U3 = CMP-0076095-1: Low-Noise 1 A, 420 kHz Transformer Driver, DBV0006A (SOT-23-6); Manufacturer: Texas Instruments; Alternate PartNumber: SN6505BDBVT; SizeAreaWB_mm2: 14.82; SizeArea_mm2: 8.12; SizeZ_mm: 1.45; Green_REACh: Passed; SizeY_mm: 2.9; Green_Lifecycle: Active; U/M: EA; CompType: IC; SizeX_mm: 2.8
U4 = CMP-0073613-3: as U17 on sheet MCU114E1_EtherCAT
U5 = CMP-0043361-3: Dual In / Single Out Autoswitching Power Mux, 2.8 to 5.5 V, -40 to 85 degC, 9-pin SON (DRB), Green (RoHS & no Sb/Br); Manufacturer: Texas Instruments; SubFamily: Power Multiplexer (MUX); IN1 Output Current(Max)(A): 1.25; IN1, IN2 Input Voltage(Min)(V): 2.8; IN2 rDS(on)(Typ)(Ohms): 0.084; Number of Inputs: 2; IN1, IN2 Input Voltage(Max)(V): 5.5; IN1 rDS(on)(Typ)(mOhm): 84; AEC Category: Q200; AEC Qualified: N; CompType: IC; SizeAreaWB_mm2: 16.0; SizeArea_mm2: 9.0; SizeX_mm: 3.0; SizeZ_mm: 1.0
U8 = CMP-0091939-1: Linear Voltage Regulator IC Positive Fixed 1 Output 300mA SOT-23-5; Manufacturer: Texas Instruments; SizeZ_mm: 1.45mm; Nominal Supply Current: 35-370uA; TJmax_C: +125°C; Output Voltage: 3.3V; Dropout Voltage: 260mV; Standoff Height: 0mm; Accuracy Percentage: 2%; AEC Qualified: No; Max Supply Voltage: 5.5V; Number Of Outputs: 1; Min Supply Voltage: 2V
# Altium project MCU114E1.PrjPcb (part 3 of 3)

## Sheet MCU114E1_XDS110_MCU.SchDoc
size 431 x 279 mm; Date: Not shown in title block; ApprovedBy: Not shown in title block; CheckedBy: Not shown in title block; Author: Not shown in title block; CompanyName: Not shown in title block; Engineer: Not shown in title block; Organization: Not shown in title block; Address1: Not shown in title block; Address2: Not shown in title block; Address3: Not shown in title block; Address4: Not shown in title block; DocumentNumber: 9; Revision: Use project parameter SCH_Rev; SheetNumber: 9; SheetTotal: 10; PageSetup: Record=PageOptions¦CenterHorizontal=True¦CenterVertical=True¦PrintScale=1.00¦XCorrection=1.00¦YCorrection=1.00¦PrintKind=0¦BorderSize=5000000¦LeftOffset=0¦BottomOffset=0¦Orientation=2¦PaperLength=1000¦PaperWidth=1000¦Scale=100¦PaperSource=15¦PrintQuality=600¦MediaType=1¦DitherType=10¦PaperKind=Letter¦PrintScaleMode=1

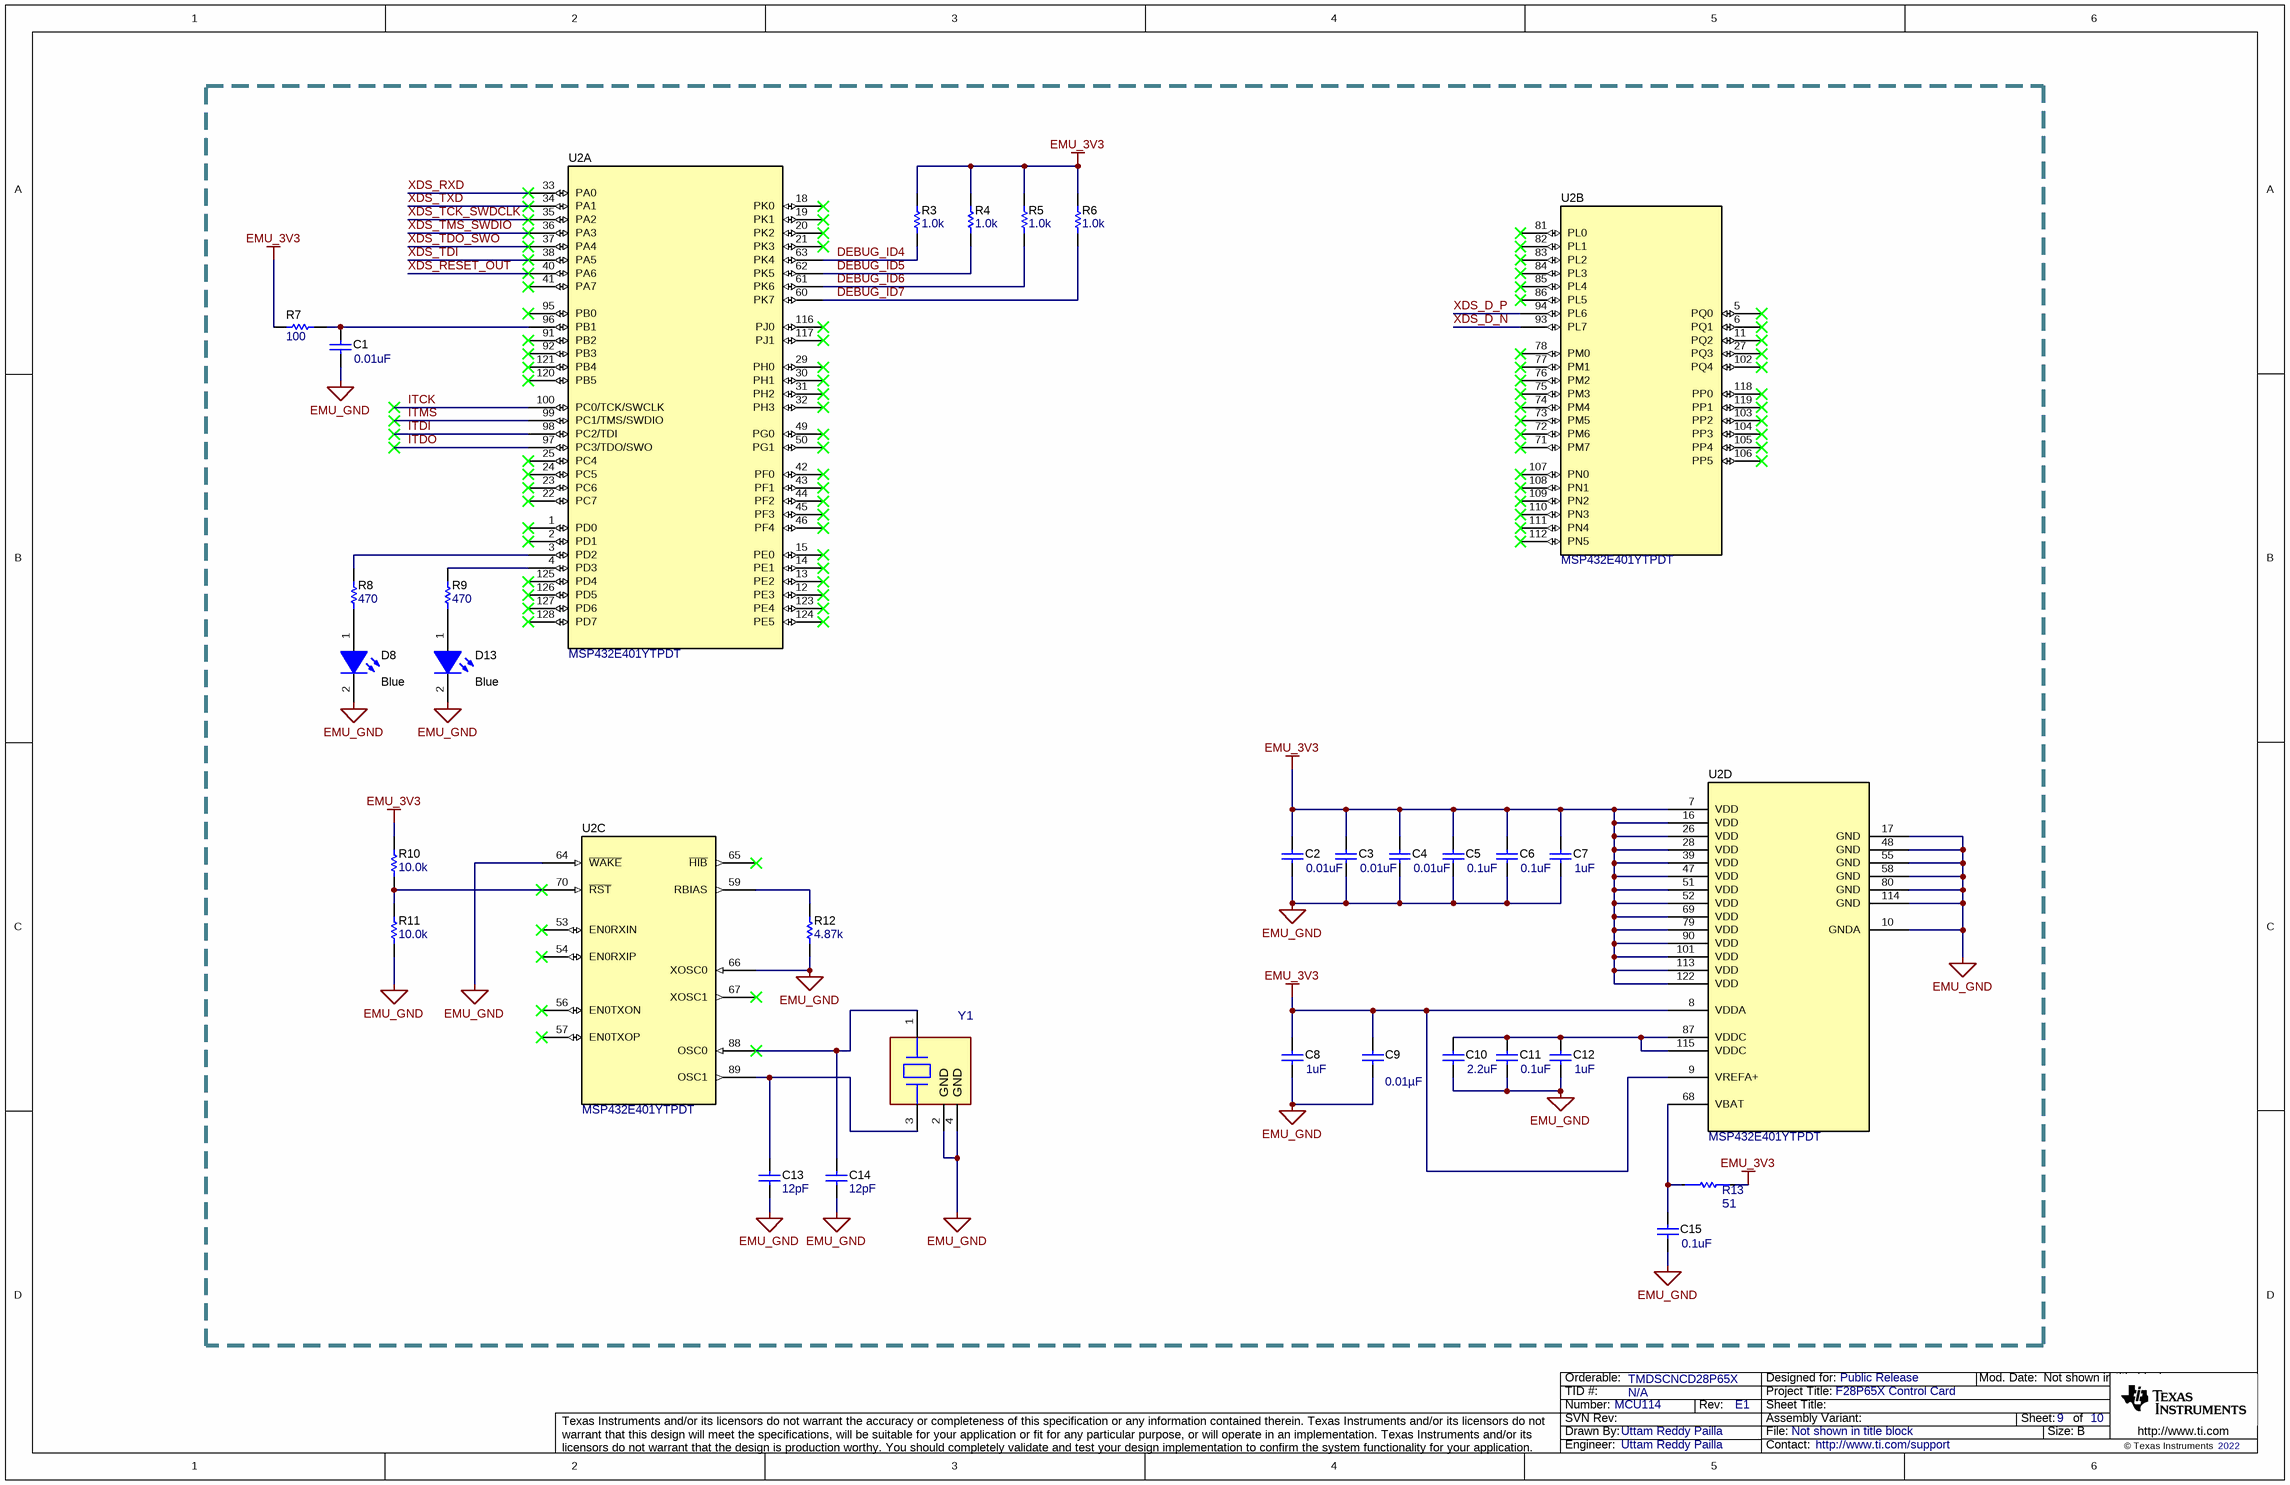
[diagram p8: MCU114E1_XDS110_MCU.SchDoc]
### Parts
C1  ValueDisplayed: 0.01uF  [0402]  (hidden comment: 885012205031)
C2  ValueDisplayed: 0.01uF  [0402]  (hidden comment: 885012205031)
C3  ValueDisplayed: 0.01uF  [0402]  (hidden comment: 885012205031)
C4  ValueDisplayed: 0.01uF  [0402]  (hidden comment: 885012205031)
C5  ValueDisplayed: 0.1uF  [0402]  (hidden comment: GRM155R60J104KA01D)
C6  ValueDisplayed: 0.1uF  [0402]  (hidden comment: GRM155R60J104KA01D)
C7  ValueDisplayed: 1uF  [0402]  (hidden comment: 885012105012)
C8  ValueDisplayed: 1uF  [0402]  (hidden comment: 885012105012)
C9  ValueDisplayed: 0.01µF  [0402]  (hidden comment: CL05B103KA5NNNC)
C10  ValueDisplayed: 2.2uF  [0402]  (hidden comment: 885012105013)
C11  ValueDisplayed: 0.1uF  [0402]  (hidden comment: GRM155R60J104KA01D)
C12  ValueDisplayed: 1uF  [0402]  (hidden comment: 885012105012)
C13  ValueDisplayed: 12pF  [0402]  (hidden comment: CL05C120JB5NNNC)
C14  ValueDisplayed: 12pF  [0402]  (hidden comment: CL05C120JB5NNNC)
C15  ValueDisplayed: 0.1uF  [0402]  (hidden comment: GRM155R60J104KA01D)
D8  value Blue  [LTST-C170TBKT_Blue]  (hidden comment: LTST-C170TBKT)
D13  value Blue  [LTST-C170TBKT_Blue]  (hidden comment: LTST-C170TBKT)
R3  ValueDisplayed: 1.0k  [0402]  (hidden comment: CRCW04021K00JNED)
R4  ValueDisplayed: 1.0k  [0402]  (hidden comment: CRCW04021K00JNED)
R5  ValueDisplayed: 1.0k  [0402]  (hidden comment: CRCW04021K00JNED)
R6  ValueDisplayed: 1.0k  [0402]  (hidden comment: CRCW04021K00JNED)
R7  ValueDisplayed: 100  [0402]  (hidden comment: CRCW0402100RJNED)
R8  ValueDisplayed: 470  [0402]  (hidden comment: ERJ-2RKF4700X)
R9  ValueDisplayed: 470  [0402]  (hidden comment: ERJ-2RKF4700X)
R10  ValueDisplayed: 10.0k  [0402]  (hidden comment: AC0402FR-0710KL)
R11  ValueDisplayed: 10.0k  [0402]  (hidden comment: AC0402FR-0710KL)
R12  ValueDisplayed: 4.87k  [0402]  (hidden comment: CRCW04024K87FKED)
R13  51  [FP-RT0402FRE0751RL_0402-MFG]
U2  MSP432E401YTPDT  [PDT0128A]  (parts A,B,C,D of 4)
Y1  830064296  [FP-830064296_SMT4_3MM4_2MM7-MFG]  (value not drawn)

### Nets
EMU_3V3: C2.1 C3.1 C4.1 C5.1 C6.1 C7.1 C8.1 C9.1 R3.2 R4.2 R5.2 R6.2 R7.1 R10.2 R13.2 U2.7(VDD) U2.8(VDDA) U2.9(VREFA+) U2.16(VDD) U2.26(VDD) U2.28(VDD) U2.39(VDD) U2.47(VDD) U2.51(VDD) U2.52(VDD) U2.69(VDD) U2.79(VDD) U2.90(VDD) U2.101(VDD) U2.113(VDD) U2.122(VDD)
EMU_GND: C1.2 C2.2 C3.2 C4.2 C5.2 C6.2 C7.2 C8.2 C9.2 C10.2 C11.2 C12.2 C13.2 C14.2 C15.2 D8.2(K) D13.2(K) R11.1 R12.1 U2.10(GNDA) U2.17(GND) U2.48(GND) U2.55(GND) U2.58(GND) U2.64(~{WAKE}) U2.66(XOSC0) U2.80(GND) U2.114(GND) Y1.2(GND) Y1.4(GND)
DEBUG_ID4: R3.1 U2.63(PK4)
DEBUG_ID5: R4.1 U2.62(PK5)
DEBUG_ID6: R5.1 U2.61(PK6)
DEBUG_ID7: R6.1 U2.60(PK7)
ITCK: U2.100(PC0/TCK/SWCLK)
ITDI: U2.98(PC2/TDI)
ITDO: U2.97(PC3/TDO/SWO)
ITMS: U2.99(PC1/TMS/SWDIO)
XDS_D_N: U2.93(PL7)
XDS_D_P: U2.94(PL6)
XDS_RESET_OUT: U2.40(PA6)
XDS_RXD: U2.33(PA0)
XDS_TCK_SWDCLK: U2.35(PA2)
XDS_TDI: U2.38(PA5)
XDS_TDO_SWO: U2.37(PA4)
XDS_TMS_SWDIO: U2.36(PA3)
XDS_TXD: U2.34(PA1)
NetC1_1: C1.1 R7.2 U2.96(PB1)
NetC10_1: C10.1 C11.1 C12.1 U2.87(VDDC) U2.115(VDDC)
NetC13_1: C13.1 U2.89(OSC1) Y1.3(2_Crystal)
NetC14_1: C14.1 U2.88(OSC0) Y1.1(1_Crystal)
NetC15_1: C15.1 R13.1 U2.68(VBAT)
NetD8_1: D8.1(A) R8.1
NetD13_1: D13.1(A) R9.1
NetR8_2: R8.2 U2.3(PD2)
NetR9_2: R9.2 U2.4(PD3)
NetR10_1: R10.1 R11.2 U2.70(~{RST})
NetR12_2: R12.2 U2.59(RBIAS)

Not connected (* = marked no-connect by the designer): U2 1(PD0)* 2(PD1)* 5(PQ0)* 6(PQ1)* 11(PQ2)* 12(PE3)* 13(PE2)* 14(PE1)* 15(PE0)* 18(PK0)* 19(PK1)* 20(PK2)* 21(PK3)* 22(PC7)* 23(PC6)* 24(PC5)* 25(PC4)* 27(PQ3)* 29(PH0)* 30(PH1)* 31(PH2)* 32(PH3)* 41(PA7)* 42(PF0)* 43(PF1)* 44(PF2)* 45(PF3)* 46(PF4)* 49(PG0)* 50(PG1)* 53(EN0RXIN)* 54(EN0RXIP)* 56(EN0TXON)* 57(EN0TXOP)* 65(~{HIB})* 67(XOSC1)* 71(PM7)* 72(PM6)* 73(PM5)* 74(PM4)* 75(PM3)* 76(PM2)* 77(PM1)* 78(PM0)* 81(PL0)* 82(PL1)* 83(PL2)* 84(PL3)* 85(PL4)* 86(PL5)* 91(PB2)* 92(PB3)* 95(PB0)* 102(PQ4)* 103(PP2)* 104(PP3)* 105(PP4)* 106(PP5)* 107(PN0)* 108(PN1)* 109(PN2)* 110(PN3)* 111(PN4)* 112(PN5)* 116(PJ0)* 117(PJ1)* 118(PP0)* 119(PP1)* 120(PB5)* 121(PB4)* 123(PE4)* 124(PE5)* 125(PD4)* 126(PD5)* 127(PD6)* 128(PD7)*

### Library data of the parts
C1-C4 = CMP-0006227-2: CAP, CERM, 0.01 uF, 16 V, +/- 10%, X7R, 0402; Manufacturer: Wurth Elektronik; TaMin_C: -55°C; Polarized: N; SizeAreaWB_mm2: 3; Value1: Unknown; U/M: EA; Value: 0.01uF; TaMax_C: 125°C; SizeZ_mm: 0.6; SizeX_mm: 1; SizeY_mm: 0.5; Value2: 16V; Cap_F: 10nF; AEC Category: Q200
C5 C6 C11 C15 = CMP-0006531-2: CAP, CERM, 0.1 uF, 6.3 V, +/- 10%, X5R, 0402; Manufacturer: MuRata; TaMin_C: -55°C; Polarized: N; SizeAreaWB_mm2: 3; Value1: Unknown; U/M: EA; Value: 0.1uF; TaMax_C: 85°C; SizeZ_mm: 0.6; SizeX_mm: 1; SizeY_mm: 0.5; Value2: 6.3V; Cap_F: 100nF; AEC Category: Q200
C7 C8 C12 = CMP-0064924-2: CAP, CERM, 1 uF, 10 V,+/- 20%, X5R, 0402; Manufacturer: Wurth Elektronik; TaMin_C: -55°C; Polarized: N; SizeAreaWB_mm2: 3; Value1: Unknown; U/M: EA; Value: 1uF; TaMax_C: 85°C; SizeZ_mm: 0.6; SizeX_mm: 1; SizeY_mm: 0.5; Value2: 10V; Cap_F: 1µF; AEC Category: Q200
C9 = CMP-0860561-1: CAP, CERM, 0.01 µF, 25 V,+/- 10%, X7R, 0402; Manufacturer: Samsung Electro-Mechanics; U/M: EA; SizeArea_mm2: 0.5; Value: 0.01uF; TaMin_C: -55°C; VDC_V: 25V; SizeZ_mm: 0.6; Polarized: N; SizeX_mm: 1; TaMax_C: 125°C; SizeAreaWB_mm2: 3; Cap_F: 10nF; AEC Category: Q200
C10 = CMP-0006222-2: CAP, CERM, 2.2 uF, 10 V, +/- 20%, X5R, 0402; Manufacturer: Wurth Elektronik; TaMin_C: -55°C; Polarized: N; SizeAreaWB_mm2: 3; Value1: Unknown; U/M: EA; Value: 2.2uF; TaMax_C: 85°C; SizeZ_mm: 0.6; SizeX_mm: 1; SizeY_mm: 0.5; Value2: 10V; Cap_F: 2.2µF; AEC Category: Q200
C13 C14 = CMP-0006345-2: CAP, CERM, 12 pF, 50 V, +/- 5%, C0G/NP0, 0402; Manufacturer: Samsung Electro-Mechanics; Polarized: N; Value: 12pF; U/M: EA; Value1: Unknown; VDC_V: 50V; TaMin_C: -55°C; TaMax_C: 125°C; SizeArea_mm2: 0.5; SizeAreaWB_mm2: 3; SizeX_mm: 1; SizeZ_mm: 0.6; AEC Category: Q200
D8 D13 = CMP-0002889-2: LED, Blue, SMD; Manufacturer: Lite-On; Type: AlInGaP; Vf_V: 3.3V; Io_A: 20mA; Value1: W
R3-R6 = CMP-0026852-3: RES, 1.0 k, 5%, 0.063 W, AEC-Q200 Grade 0, 0402; Manufacturer: Vishay-Dale; Power_W: 63mW; TempCo: 200 ppm/C; Value_Code: 1k00; Value: 1.0k; EIA_Code: E24; Res_ohm: 1k; SizeX_mm: 1; SizeY_mm: 0.5; SizeZ_mm: 0.6; Value2: 0.063W; AEC Qualified: Y; VDC_V: 50V; AEC Category: Q200; AEC Grade: 0
R7 = CMP-0026824-3: RES, 100, 5%, 0.063 W, AEC-Q200 Grade 0, 0402; Manufacturer: Vishay-Dale; Power_W: 63mW; TempCo: 200 ppm/C; Value_Code: 100R; Value: 100; EIA_Code: E24; SizeX_mm: 1; SizeY_mm: 0.5; SizeZ_mm: 0.6; Value2: 0.063W; AEC Qualified: Y; VDC_V: 50V; AEC Category: Q200; AEC Grade: 0
R8 R9 = CMP-0026699-1: RES, 470, 1%, 0.1 W, AEC-Q200 Grade 0, 0402; Manufacturer: Panasonic; Value: 470; Value_Code: 470R; Power_W: 100mW; Value2: 0.1W; VDC_V: 50V; TempCo: 100 ppm/C; SizeArea_mm2: 0.5; SizeX_mm: 1; SizeZ_mm: 0.6; U/M: EA; AEC Category: Q200; AEC Qualified: Y; AEC Grade: 0
R10 R11 = CMP-0077731-1: RES, 10.0 k, 1%, 0.063 W, AEC-Q200 Grade 0, 0402; Manufacturer: Yageo America; Power_W: 63mW; TempCo: 100 ppm/C; Value_Code: 10k0; U/M: EA; Value: 10.0k; EIA_Code: E96; Res_ohm: 10k; SizeX_mm: 1.0; SizeY_mm: 0.5; SizeZ_mm: 0.6; Value2: 0.063W; AEC Qualified: Y; VDC_V: 50V; AEC Grade: 0; AEC Category: Q200
R12 = CMP-0026413-2: RES, 4.87 k, 1%, 0.063 W, AEC-Q200 Grade 0, 0402; Manufacturer: Vishay-Dale; Power_W: 63mW; TempCo: 100 ppm/C; Value_Code: 4k87; Value: 4.87k; EIA_Code: E96; SizeX_mm: 1; SizeY_mm: 0.5; SizeZ_mm: 0.6; Value2: 0.063W; AEC Qualified: Y; VDC_V: 50V; AEC Category: Q200; AEC Grade: 0
R13 = CMP-0092664-1: 51 Ohms ±1% 0.063W, 1/16W Chip Resistor 0402 (1005 Metric) - Thin Film; PartNumber: RT0402FRE0751RL; Manufacturer: Yageo; VDC_V: 50V; AEC Qualified: No; Power_W: 63mW; TempCo: 50ppm/°C; SizeZ_mm: 0.35mm
U2 = CMP-0077953-1: MSP432E401YTPDT, PDT0128A (TQFP-128); Alternate PartNumber: MSP432E401YTPDTR; Alternate Manufacturer: Texas Instruments; SizeAreaWB_mm2: 324; SizeZ_mm: 1.2; SizeX_mm: 16; SizeArea_mm2: 256; CompType: IC; AEC Qualified: N; AEC Category: Q200
Y1 = CMP-0094478-1: Crystal 16 MHz ±20ppm Crystal 8pF 70 Ohms 4-SMD, No Lead; Manufacturer: Wurth; SizeZ_mm: 0.8mm; Frequency_Fixed: 16MHz; Esr: 70

## Sheet MCU114E1_Emulator_Interface.SchDoc
size 431 x 279 mm; Date: Not shown in title block; ApprovedBy: Not shown in title block; CheckedBy: Not shown in title block; Author: Not shown in title block; CompanyName: Not shown in title block; Engineer: Not shown in title block; Organization: Not shown in title block; Address1: Not shown in title block; Address2: Not shown in title block; Address3: Not shown in title block; Address4: Not shown in title block; DocumentNumber: 10; Revision: Use project parameter SCH_Rev; SheetNumber: 10; SheetTotal: 11; PageSetup: Record=PageOptions¦CenterHorizontal=True¦CenterVertical=True¦PrintScale=1.00¦XCorrection=1.00¦YCorrection=1.00¦PrintKind=0¦BorderSize=5000000¦LeftOffset=0¦BottomOffset=0¦Orientation=2¦PaperLength=1000¦PaperWidth=1000¦Scale=100¦PaperSource=15¦PrintQuality=600¦MediaType=1¦DitherType=10¦PaperKind=Letter¦PrintScaleMode=1

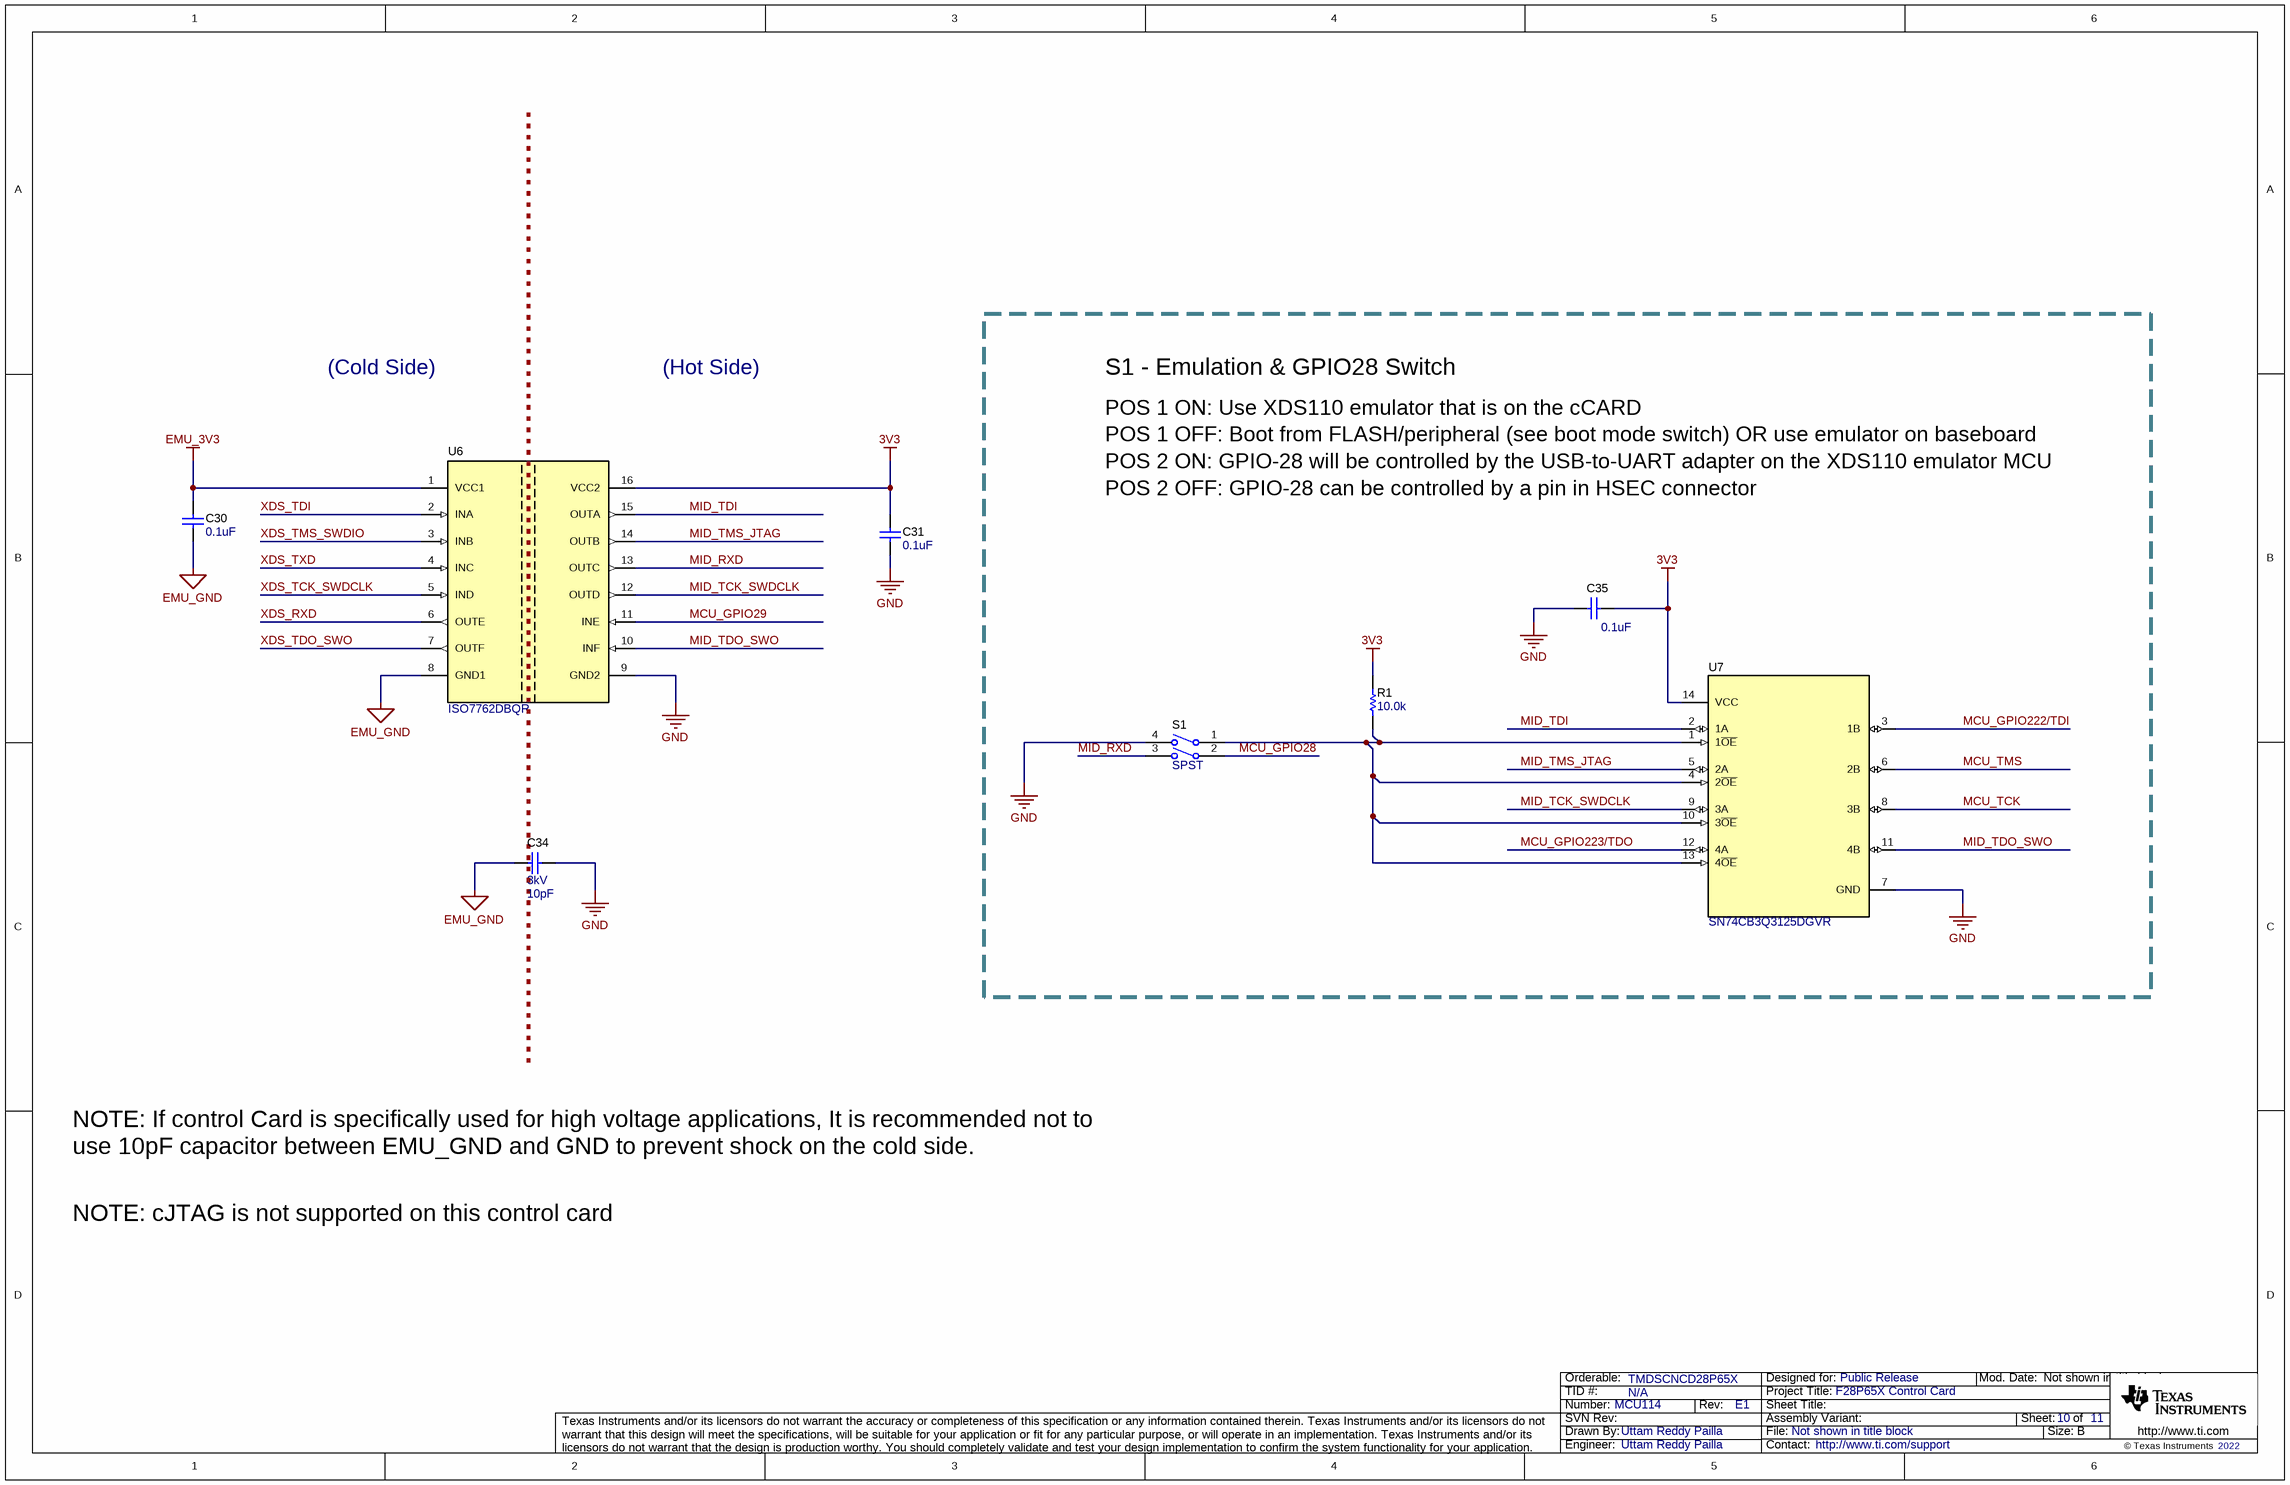
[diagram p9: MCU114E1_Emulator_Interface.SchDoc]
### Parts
C30  ValueDisplayed: 0.1uF  [0402]  (hidden comment: 885012205037)
C31  ValueDisplayed: 0.1uF  [0402]  (hidden comment: 885012205037)
C34  VDC_V: 3kV  ValueDisplayed: 10pF  [1812_180]  (hidden comment: C1812C100JHGACTU)
C35  ValueDisplayed: 0.1uF  [0402]  (hidden comment: 885012205037)
R1  ValueDisplayed: 10.0k  [0402]  (hidden comment: AC0402FR-0710KL)
S1  Circuit: SPST  [SW_218-2LP]  (hidden comment: 218-2LPST)
U6  ISO7762DBQR  [DBQ0016A_N]
U7  SN74CB3Q3125DGVR  [DGV0014A_N]

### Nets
3V3: C31.1 C35.1 R1.2 U6.16(VCC2) U7.14(VCC)
EMU_3V3: C30.1 U6.1(VCC1)
EMU_GND: C30.2 C34.2 U6.8(GND1)
GND: C31.2 C34.1 C35.2 S1.4 U6.9(GND2) U7.7(GND)
MCU_GPIO28: S1.2
MCU_GPIO29: U6.11(INE)
MCU_GPIO222/TDI: U7.3(1B)
MCU_GPIO223/TDO: U7.12(4A)
MCU_TCK: U7.8(3B)
MCU_TMS: U7.6(2B)
MID_RXD: S1.3 U6.13(OUTC)
MID_TCK_SWDCLK: U6.12(OUTD) U7.9(3A)
MID_TDI: U6.15(OUTA) U7.2(1A)
MID_TDO_SWO: U6.10(INF) U7.11(4B)
MID_TMS_JTAG: U6.14(OUTB) U7.5(2A)
XDS_RXD: U6.6(OUTE)
XDS_TCK_SWDCLK: U6.5(IND)
XDS_TDI: U6.2(INA)
XDS_TDO_SWO: U6.7(OUTF)
XDS_TMS_SWDIO: U6.3(INB)
XDS_TXD: U6.4(INC)
NetR1_1: R1.1 S1.1 U7.1(1~{OE}) U7.4(2~{OE}) U7.10(3~{OE}) U7.13(4~{OE})

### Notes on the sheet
- S1 - Emulation & GPIO28 Switch
- (Cold Side)
- (Hot Side)
- POS 1 ON: Use XDS110 emulator that is on the cCARD
- POS 1 OFF: Boot from FLASH/peripheral (see boot mode switch) OR use emulator on baseboard
- POS 2 ON: GPIO-28 will be controlled by the USB-to-UART adapter on the XDS110 emulator MCU
- POS 2 OFF: GPIO-28 can be controlled by a pin in HSEC connector
- NOTE: If control Card is specifically used for high voltage applications, It is recommended not to use 10pF capacitor between EMU_GND and GND to prevent shock on the cold side.
- NOTE: cJTAG is not supported on this control card

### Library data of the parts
C30 C31 C35 = CMP-0006228-2: CAP, CERM, 0.1 uF, 16 V, +/- 10%, X7R, 0402; Manufacturer: Wurth Elektronik; TaMin_C: -55°C; Polarized: N; SizeAreaWB_mm2: 3; Value1: Unknown; U/M: EA; Value: 0.1uF; TaMax_C: 125°C; SizeZ_mm: 0.6; SizeX_mm: 1; SizeY_mm: 0.5; Value2: 16V; Cap_F: 100nF; AEC Category: Q200
C34 = CMP-0082066-1: CAP, CERM, 10 pF, 3000 V,+/- 5%, C0G/NP0, AEC-Q200 Grade 1, 1812; Manufacturer: Kemet; SizeAreaWB_mm2: 23.1; SizeArea_mm2: 14.4; AEC Qualified: Y; AEC Category: Q200; Value: 10pF; TaMax_C: 125°C; SizeZ_mm: 1.8; AEC Grade: 1; Polarized: N; TaMin_C: -55°C; SizeY_mm: 3.2; Value2: 3000V; U/M: EA; SizeX_mm: 4.5; Cap_Case: 1812
R1 = CMP-0077731-1: as R10 on sheet MCU114E1_XDS110_MCU
S1 = CMP-0002230-1: Switch, SPST, 2 Pos, 25mA, 24VDC, SMD; Manufacturer: CTS Electrocomponents; VDC_V: 24V; SwitchFunction: Off-On; PositionCount: 2; CurrentRating_mA: 25A
U6 = CMP-0067607-3: High Speed, Robust EMC, Reinforced Six-Channel Digital Isolator, DBQ0016A (SSOP-16); Manufacturer: Texas Instruments; SizeX_mm: 6.0; SizeY_mm: 10.0; CompType: IC; SizeZ_mm: 1.75; SizeArea_mm2: 60.0; SizeAreaWB_mm2: 96.0; U/M: EA; AEC Category: Q200; AEC Qualified: N
U7 = CMP-0066249-2: Quadruple FET 2.5-V/3.3-V Low-Voltage High-Bandwidth Bus Switch, DGV0014A (TVSOP-14); Alternate Manufacturer: Texas Instruments; SizeArea_mm2: 23.04; SizeX_mm: 6.4; SizeAreaWB_mm2: 47.04; CompType: IC; SizeZ_mm: 1.2; AEC Category: Q200; Rating: Catalog; SizeY_mm: 3.6; AEC Qualified: N

## Sheet MCU114E1_EVM_Hardware.SchDoc
size 431 x 279 mm; Date: Not shown in title block; ApprovedBy: Not shown in title block; CheckedBy: Not shown in title block; Author: Not shown in title block; CompanyName: Not shown in title block; Engineer: Not shown in title block; Organization: Not shown in title block; Address1: Not shown in title block; Address2: Not shown in title block; Address3: Not shown in title block; Address4: Not shown in title block; DocumentNumber: 11; Revision: Use project parameter SCH_Rev; SheetNumber: 11; SheetTotal: 11; PageSetup: Record=PageOptions¦CenterHorizontal=True¦CenterVertical=True¦PrintScale=1.00¦XCorrection=1.00¦YCorrection=1.00¦PrintKind=0¦BorderSize=5000000¦LeftOffset=0¦BottomOffset=0¦Orientation=2¦PaperLength=1000¦PaperWidth=1000¦Scale=100¦PaperSource=15¦PrintQuality=600¦MediaType=1¦DitherType=10¦PaperKind=Letter¦PrintScaleMode=1

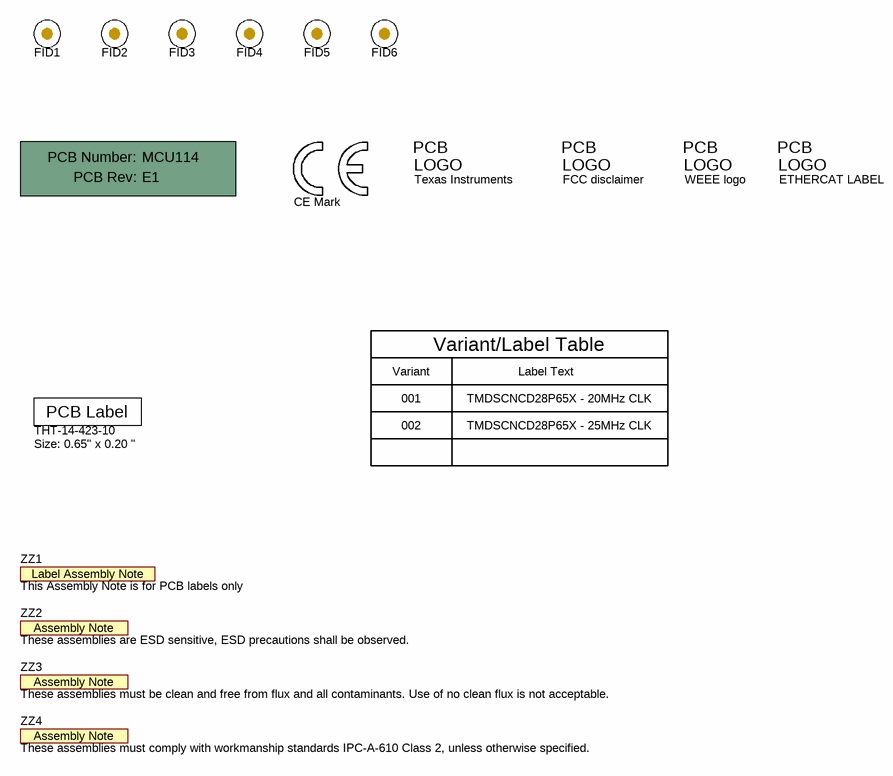
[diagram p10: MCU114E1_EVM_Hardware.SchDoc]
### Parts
!PCB1  Printed Circuit Board  (value not drawn)  (mechanical)
FID1  Fiducial  [Fiducial10-20]  (value not drawn)
FID2  Fiducial  [Fiducial10-20]  (value not drawn)
FID3  Fiducial  [Fiducial10-20]  (value not drawn)
FID4  Fiducial  [Fiducial10-20]  (value not drawn)
FID5  Fiducial  [Fiducial10-20]  (value not drawn)
FID6  Fiducial  [Fiducial10-20]  (value not drawn)
LBL1  THT-14-423-10  Note: Size: 0.65" x 0.20 "  [Label_650x200]
Logo1  CE Mark  [CE_Mark_5mm]  (no BOM)
Logo2  Texas Instruments  [TI_Stacked_Overlay_Small]  (no BOM)
Logo3  FCC disclaimer  [FCC_disclaimer]  (no BOM)
Logo4  WEEE logo  [WEEE_Minimum]  (no BOM)
Logo5  ETHERCAT LABEL  [EtherCAT_label]  (no BOM)
ZZ1  This Assembly Note is for PCB labels only  [AssemblyNoteLabel]  (no BOM)
ZZ2  These assemblies are ESD sensitive, ESD precautions shall be observed.  [AssemblyNote]  (no BOM)
ZZ3  These assemblies must be clean and free from flux and all contaminants. Use of no clean flux is not acceptable.  [AssemblyNote]  (no BOM)
ZZ4  These assemblies must comply with workmanship standards IPC-A-610 Class 2, unless otherwise specified.  [AssemblyNote]  (no BOM)

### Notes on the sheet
- Variant/Label Table
- Variant
- 001
- 002
- Label Text
- TMDSCNCD28P65X - 20MHz CLK
- TMDSCNCD28P65X - 25MHz CLK

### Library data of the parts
!PCB1 = CMP-0003618-2: Manufacturer: Any; PartNumber: MCU114
FID1-FID6 = CMP-0077181-1: Fiducial mark.  There is nothing to buy or mount.
LBL1 = CMP-0003625-1: Thermal Transfer Printable Labels, 0.650" W x 0.200" H - 10,000 per roll; Manufacturer: Brady
Logo1 = CMP-0074844-1: SymbolCreator: a0412235
Logo2 = CMP-0074838-1: Texas Instrument Corporate Signature; SymbolCreator: a0412235; Lib Reference: TI_Logo; Library Reference: Logo
Logo3 = CMP-0074847-1: FCC_disclaimer
Logo4 = CMP-0074769-1
Logo5 = CMP-0084011-3: EtherCAT logo
ZZ1 = CMP-0003616-3
ZZ2 = CMP-0077236-1
ZZ3 = CMP-0077237-1
ZZ4 = CMP-0077238-1

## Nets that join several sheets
1V2: MCU114E1_GPIOs (EC1.118), MCU114E1_Power (C84.1 L5.1 R101.2)
3V3: MCU114E1_GPIOs (EC1.119 R204.2 R205.1), MCU114E1_Support (31 pins), MCU114E1_Power (6 pins), MCU114E1_EtherCAT (24 pins), MCU114E1_USB (R71.2), MCU114E1_Emulator_Interface (5 pins)
5V0: MCU114E1_Support (C51.1 U11.2), MCU114E1_Power (9 pins), MCU114E1_XDS110_USB_Power (R20.2 R21.2 R28.2 R29.2)
EMU_3V3: MCU114E1_XDS110_USB_Power (C17.1 R14.1 TP2.1 U8.5), MCU114E1_XDS110_MCU (31 pins), MCU114E1_Emulator_Interface (C30.1 U6.1)
EMU_GND: MCU114E1_XDS110_USB_Power (27 pins), MCU114E1_XDS110_MCU (30 pins), MCU114E1_Emulator_Interface (C30.2 C34.2 U6.8)
GND: MCU114E1_GPIOs (15 pins), MCU114E1_Support (40 pins), MCU114E1_ADC (48 pins), MCU114E1_Power (66 pins), MCU114E1_EtherCAT (69 pins), MCU114E1_USB (20 pins), MCU114E1_XDS110_USB_Power (16 pins), MCU114E1_Emulator_Interface (6 pins)
HSEC_5V0: MCU114E1_GPIOs (6 pins), MCU114E1_Power (TP11.1), MCU114E1_XDS110_USB_Power (6 pins)
USB_5V0: MCU114E1_Power (R93.2), MCU114E1_USB (C46.1 C47.1 R90.2 U14.5)
VDD_1V2: MCU114E1_Support (U12.10), MCU114E1_Power (16 pins)
VDDA_3V3: MCU114E1_ADC (5 pins), MCU114E1_Power (6 pins)
ERRORSTS: MCU114E1_GPIOs (EC2.178), MCU114E1_Support (R38.2 TP4.1 U1.P16)
HSEC_ADC-VREFHI: MCU114E1_GPIOs (EC1.45), MCU114E1_ADC (S7.4)
HSEC_ADC_A0A1_N: MCU114E1_GPIOs (EC1.11), MCU114E1_ADC (R176.2 U9.2 U9.13)
HSEC_ADC_A0A1_P: MCU114E1_GPIOs (EC1.9), MCU114E1_ADC (R175.2 U9.1 U9.14)
HSEC_ADC_A2A3_N: MCU114E1_GPIOs (EC1.17), MCU114E1_ADC (R178.2 U9.4 U9.11)
HSEC_ADC_A2A3_P: MCU114E1_GPIOs (EC1.15), MCU114E1_ADC (R177.2 U9.3 U9.12)
HSEC_ADC_A4A5_N: MCU114E1_GPIOs (EC1.23), MCU114E1_ADC (R180.2 U9.7 U9.8)
HSEC_ADC_A4A5_P: MCU114E1_GPIOs (EC1.21), MCU114E1_ADC (R179.2 U9.6 U9.9)
HSEC_ADC_A8A9_N: MCU114E1_GPIOs (EC1.36), MCU114E1_ADC (R182.2 U21.4 U21.11)
HSEC_ADC_A8A9_P: MCU114E1_GPIOs (EC1.34), MCU114E1_ADC (R181.2 U21.3 U21.12)
HSEC_ADC_A10A11_N: MCU114E1_GPIOs (EC1.42), MCU114E1_ADC (R184.2 U21.7 U21.8)
HSEC_ADC_A10A11_P: MCU114E1_GPIOs (EC1.40), MCU114E1_ADC (R183.2 U21.6 U21.9)
HSEC_ADC_A14B14C14A15B15C15_N: MCU114E1_GPIOs (EC1.27), MCU114E1_ADC (R186.2 U20.2 U20.13)
HSEC_ADC_A14B14C14A15B15C15_P: MCU114E1_GPIOs (EC1.25), MCU114E1_ADC (R185.2 U20.1 U20.14)
HSEC_ADC_B0B1_N: MCU114E1_GPIOs (EC1.14), MCU114E1_ADC (R189.2 U22.2 U22.13)
HSEC_ADC_B0B1_P: MCU114E1_GPIOs (EC1.12), MCU114E1_ADC (R188.2 U22.1 U22.14)
HSEC_ADC_B2B3_N: MCU114E1_GPIOs (EC1.20), MCU114E1_ADC (R191.2 U22.4 U22.11)
HSEC_ADC_B2B3_P: MCU114E1_GPIOs (EC1.18), MCU114E1_ADC (R190.2 U22.3 U22.12)
HSEC_ADC_B4B5_N: MCU114E1_GPIOs (EC1.26), MCU114E1_ADC (R193.2 U22.7 U22.8)
HSEC_ADC_B4B5_P: MCU114E1_GPIOs (EC1.24), MCU114E1_ADC (R192.2 U22.6 U22.9)
HSEC_ADC_C2C3_N: MCU114E1_GPIOs (EC1.33), MCU114E1_ADC (R196.2 U20.4 U20.11)
HSEC_ADC_C2C3_P: MCU114E1_GPIOs (EC1.31), MCU114E1_ADC (R195.2 U20.3 U20.12)
HSEC_ADC_C4: MCU114E1_GPIOs (EC1.30), MCU114E1_ADC (R197.2 U21.2 U21.13)
HSEC_ADC_C6: MCU114E1_GPIOs (EC1.28), MCU114E1_ADC (R201.2 U21.1 U21.14)
HSEC_ADC_C10C11_N: MCU114E1_GPIOs (EC1.39), MCU114E1_ADC (R173.2 U20.7 U20.8)
HSEC_ADC_C10C11_P: MCU114E1_GPIOs (EC1.37), MCU114E1_ADC (R172.2 U20.6 U20.9)
HSEC_GPIO11: MCU114E1_GPIOs (EC1.63), MCU114E1_Support (R96.1)
HSEC_GPIO12: MCU114E1_GPIOs (EC1.58), MCU114E1_Support (R45.2)
HSEC_GPIO13: MCU114E1_GPIOs (EC1.60), MCU114E1_Support (R47.2)
HSEC_GPIO25: MCU114E1_GPIOs (EC1.77), MCU114E1_Support (R98.1)
HSEC_GPIO26: MCU114E1_GPIOs (EC1.79), MCU114E1_Support (R50.2)
HSEC_GPIO27: MCU114E1_GPIOs (EC1.81), MCU114E1_Support (R56.2)
MCU_D_N: MCU114E1_Support (U1.D16), MCU114E1_USB (R81.2)
MCU_D_P: MCU114E1_Support (U1.E16), MCU114E1_USB (R80.2)
MCU_GPIO11: MCU114E1_GPIOs (U1.E4), MCU114E1_Support (J3.2 R96.2)
MCU_GPIO12: MCU114E1_GPIOs (U1.G4), MCU114E1_Support (J3.1 R45.1)
MCU_GPIO13: MCU114E1_GPIOs (U1.A3), MCU114E1_Support (J3.3 R47.1)
MCU_GPIO19: MCU114E1_GPIOs (U1.B2), MCU114E1_EtherCAT (R92.2)
MCU_GPIO25: MCU114E1_GPIOs (U1.A10), MCU114E1_Support (J3.6 R98.2)
MCU_GPIO26: MCU114E1_GPIOs (U1.L11), MCU114E1_Support (J3.5 R50.1)
MCU_GPIO27: MCU114E1_GPIOs (U1.G13), MCU114E1_Support (J3.7 R56.1)
MCU_GPIO28: MCU114E1_GPIOs (EC1.76 U1.N11), MCU114E1_Emulator_Interface (S1.2)
MCU_GPIO29: MCU114E1_GPIOs (EC1.78 U1.P11), MCU114E1_Emulator_Interface (U6.11)
MCU_GPIO31: MCU114E1_GPIOs (EC1.82 U1.D8), MCU114E1_Support (R39.1 U10.1)
MCU_GPIO34: MCU114E1_GPIOs (EC1.86 U1.P10), MCU114E1_Support (R40.1 U10.3)
MCU_GPIO44: MCU114E1_GPIOs (U1.J12), MCU114E1_USB (9 pins)
MCU_GPIO46: MCU114E1_GPIOs (U1.F14), MCU114E1_USB (R31.2 R79.1)
MCU_GPIO58: MCU114E1_GPIOs (U1.L13), MCU114E1_EtherCAT (RJ1.12)
MCU_GPIO59: MCU114E1_GPIOs (U1.L14), MCU114E1_EtherCAT (RJ2.12)
MCU_GPIO63: MCU114E1_GPIOs (U1.K14), MCU114E1_EtherCAT (R158.1 R162.2)
MCU_GPIO64: MCU114E1_GPIOs (U1.K13), MCU114E1_EtherCAT (R147.2 R150.1)
MCU_GPIO69: MCU114E1_GPIOs (U1.B16), MCU114E1_EtherCAT (R148.1)
MCU_GPIO70: MCU114E1_GPIOs (U1.C15), MCU114E1_EtherCAT (R149.1 R161.2)
MCU_GPIO71: MCU114E1_GPIOs (U1.B15), MCU114E1_EtherCAT (R130.1 R154.1)
MCU_GPIO72: MCU114E1_GPIOs (EC2.139 U1.A15), MCU114E1_Support (R62.1)
MCU_GPIO84: MCU114E1_GPIOs (EC2.151 U1.D9), MCU114E1_Support (R63.1)
MCU_GPIO100: MCU114E1_GPIOs (U1.F4), MCU114E1_Support (J2.3)
MCU_GPIO101: MCU114E1_GPIOs (U1.N9), MCU114E1_Support (J2.7)
MCU_GPIO102: MCU114E1_GPIOs (U1.C13), MCU114E1_Support (J2.5)
MCU_GPIO103: MCU114E1_GPIOs (U1.G12), MCU114E1_Support (J2.2 R36.1)
MCU_GPIO115: MCU114E1_GPIOs (EC2.169 U1.P9), MCU114E1_Support (R212.1)
MCU_GPIO116: MCU114E1_GPIOs (EC2.170 U1.H11), MCU114E1_Support (R78.1)
MCU_GPIO120: MCU114E1_GPIOs (U1.M11), MCU114E1_USB (R85.2)
MCU_GPIO123: MCU114E1_GPIOs (U1.M7), MCU114E1_EtherCAT (R108.2 U25.21)
MCU_GPIO124: MCU114E1_GPIOs (U1.L8), MCU114E1_EtherCAT (R142.2 U26.21)
MCU_GPIO129: MCU114E1_GPIOs (U1.L9), MCU114E1_EtherCAT (R91.2)
MCU_GPIO130: MCU114E1_GPIOs (U1.T10), MCU114E1_EtherCAT (R146.2 R155.1)
MCU_GPIO131: MCU114E1_GPIOs (U1.N13), MCU114E1_EtherCAT (R203.2)
MCU_GPIO132: MCU114E1_GPIOs (U1.T14), MCU114E1_EtherCAT (R144.2)
MCU_GPIO134: MCU114E1_GPIOs (U1.R14), MCU114E1_EtherCAT (R110.2)
MCU_GPIO141: MCU114E1_GPIOs (U1.H13), MCU114E1_EtherCAT (R145.1 R152.1)
MCU_GPIO142: MCU114E1_GPIOs (U1.H14), MCU114E1_EtherCAT (R133.1 R153.1)
MCU_GPIO145: MCU114E1_GPIOs (U1.H15), MCU114E1_EtherCAT (R139.1 U18.1)
MCU_GPIO146: MCU114E1_GPIOs (U1.H16), MCU114E1_EtherCAT (R140.1 U18.3)
MCU_GPIO148: MCU114E1_GPIOs (U1.C12), MCU114E1_EtherCAT (R129.2 RJ1.2 U25.31)
MCU_GPIO149: MCU114E1_GPIOs (U1.B12), MCU114E1_EtherCAT (R163.1 RJ2.2 U26.31)
MCU_GPIO150: MCU114E1_GPIOs (U1.A12), MCU114E1_EtherCAT (R105.1 U16.5)
MCU_GPIO151: MCU114E1_GPIOs (U1.F11), MCU114E1_EtherCAT (R106.1 U16.6)
MCU_GPIO152: MCU114E1_GPIOs (U1.E11), MCU114E1_EtherCAT (U25.12 U26.12)
MCU_GPIO153: MCU114E1_GPIOs (U1.D11), MCU114E1_EtherCAT (R107.1 U25.11 U26.11)
MCU_GPIO154: MCU114E1_GPIOs (U1.C11), MCU114E1_Support (R59.1 R64.1)
MCU_GPIO155: MCU114E1_GPIOs (U1.B11), MCU114E1_EtherCAT (R32.1 R141.1 U25.32 U26.32)
MCU_GPIO156: MCU114E1_GPIOs (U1.A11), MCU114E1_EtherCAT (R58.2)
MCU_GPIO157: MCU114E1_GPIOs (U1.E10), MCU114E1_EtherCAT (R112.2 R120.1)
MCU_GPIO158: MCU114E1_GPIOs (U1.D10), MCU114E1_EtherCAT (R87.2)
MCU_GPIO159: MCU114E1_GPIOs (U1.C10), MCU114E1_EtherCAT (R86.2)
MCU_GPIO160: MCU114E1_GPIOs (U1.B10), MCU114E1_EtherCAT (R84.2)
MCU_GPIO161: MCU114E1_GPIOs (U1.E9), MCU114E1_EtherCAT (R83.2)
MCU_GPIO162: MCU114E1_GPIOs (U1.A8), MCU114E1_EtherCAT (R115.1 R127.2)
MCU_GPIO163: MCU114E1_GPIOs (U1.B8), MCU114E1_EtherCAT (R114.1)
MCU_GPIO164: MCU114E1_GPIOs (U1.C8), MCU114E1_EtherCAT (R88.1 R119.1)
MCU_GPIO165: MCU114E1_GPIOs (U1.F6), MCU114E1_EtherCAT (R126.1 R128.2)
MCU_GPIO166: MCU114E1_GPIOs (U1.B5), MCU114E1_EtherCAT (R113.2 R116.1)
MCU_GPIO167: MCU114E1_GPIOs (U1.E5), MCU114E1_EtherCAT (R111.1 R117.1)
MCU_GPIO168: MCU114E1_GPIOs (U1.F5), MCU114E1_EtherCAT (R89.1 R118.1)
MCU_GPIO222/TDI: MCU114E1_GPIOs (EC1.8), MCU114E1_Support (U1.T12), MCU114E1_Emulator_Interface (U7.3)
MCU_GPIO223/TDO: MCU114E1_GPIOs (EC1.6), MCU114E1_Support (U1.R12), MCU114E1_Emulator_Interface (U7.12)
MCU_TCK: MCU114E1_GPIOs (EC1.5), MCU114E1_Support (U1.R13), MCU114E1_Emulator_Interface (U7.8)
MCU_TMS: MCU114E1_GPIOs (EC1.3), MCU114E1_Support (R202.1 U1.T13), MCU114E1_Emulator_Interface (U7.6)
MCU_XRSn: MCU114E1_GPIOs (EC1.120), MCU114E1_Support (8 pins), MCU114E1_Power (R82.1)
PHY0_CLK: MCU114E1_Support (R59.2 R60.1), MCU114E1_EtherCAT (U25.9)
PHY1_CLK: MCU114E1_Support (R64.2 R66.1), MCU114E1_EtherCAT (U26.9)
XDS_D_N: MCU114E1_XDS110_USB_Power (J1.A7 J1.B7 U4.2 U4.9), MCU114E1_XDS110_MCU (U2.93)
XDS_D_P: MCU114E1_XDS110_USB_Power (J1.A6 J1.B6 U4.1 U4.10), MCU114E1_XDS110_MCU (U2.94)
XDS_RXD: MCU114E1_XDS110_MCU (U2.33), MCU114E1_Emulator_Interface (U6.6)
XDS_TCK_SWDCLK: MCU114E1_XDS110_MCU (U2.35), MCU114E1_Emulator_Interface (U6.5)
XDS_TDI: MCU114E1_XDS110_MCU (U2.38), MCU114E1_Emulator_Interface (U6.2)
XDS_TDO_SWO: MCU114E1_XDS110_MCU (U2.37), MCU114E1_Emulator_Interface (U6.7)
XDS_TMS_SWDIO: MCU114E1_XDS110_MCU (U2.36), MCU114E1_Emulator_Interface (U6.3)
XDS_TXD: MCU114E1_XDS110_MCU (U2.34), MCU114E1_Emulator_Interface (U6.4)

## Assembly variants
001: not fitted C19 C20 C34 C41 C42 C44 C46 C52 C91 C92 C93 C94 C107 C108 C109 C110 C126 C128 C129 C130 C131 C132 C133 C134 C135 C136 C137 C138 C139 C140 C141 C142 C143 C144 C145 C146 C147 C148 C149 C150 C151 FID1 FID2 FID3 FID4 FID5 FID6 R11 R15 R28 R29 R41 R48 R55 R59 R64 R69 R71 R74 R75 R76 R77 R104
002: not fitted C19 C20 C34 C41 C42 C44 C46 C52 C91 C92 C93 C94 C107 C108 C109 C110 C126 C128 C129 C130 C131 C132 C133 C134 C135 C136 C137 C138 C139 C140 C141 C142 C143 C144 C145 C146 C147 C148 C149 C150 C151 FID1 FID2 FID3 FID4 FID5 FID6 R11 R15 R28 R29 R41 R48 R55 R59 R64 R69 R70 R71 R74 R76 R77 R104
